VERSION 5.7 ;
BUSBITCHARS "[]" ;
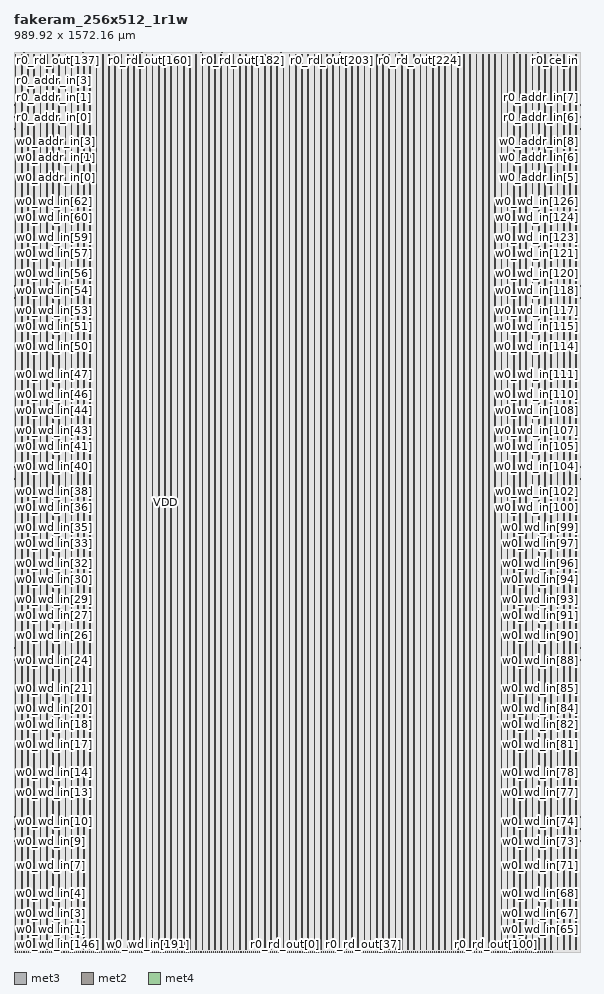
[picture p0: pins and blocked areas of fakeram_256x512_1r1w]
MACRO fakeram_256x512_1r1w
  FOREIGN fakeram_256x512_1r1w 0 0 ;
  SYMMETRY X Y R90 ;
  SIZE 989.920 BY 1572.160 ;
  CLASS BLOCK ;
  PIN w0_wd_in[0]
    DIRECTION INPUT ;
    USE SIGNAL ;
    SHAPE ABUTMENT ;
    PORT
      LAYER met3 ;
      RECT 0.000 3.930 0.900 4.230 ;
    END
  END w0_wd_in[0]
  PIN w0_wd_in[1]
    DIRECTION INPUT ;
    USE SIGNAL ;
    SHAPE ABUTMENT ;
    PORT
      LAYER met3 ;
      RECT 0.000 25.010 0.900 25.310 ;
    END
  END w0_wd_in[1]
  PIN w0_wd_in[2]
    DIRECTION INPUT ;
    USE SIGNAL ;
    SHAPE ABUTMENT ;
    PORT
      LAYER met3 ;
      RECT 0.000 46.090 0.900 46.390 ;
    END
  END w0_wd_in[2]
  PIN w0_wd_in[3]
    DIRECTION INPUT ;
    USE SIGNAL ;
    SHAPE ABUTMENT ;
    PORT
      LAYER met3 ;
      RECT 0.000 67.170 0.900 67.470 ;
    END
  END w0_wd_in[3]
  PIN w0_wd_in[4]
    DIRECTION INPUT ;
    USE SIGNAL ;
    SHAPE ABUTMENT ;
    PORT
      LAYER met3 ;
      RECT 0.000 88.250 0.900 88.550 ;
    END
  END w0_wd_in[4]
  PIN w0_wd_in[5]
    DIRECTION INPUT ;
    USE SIGNAL ;
    SHAPE ABUTMENT ;
    PORT
      LAYER met3 ;
      RECT 0.000 109.330 0.900 109.630 ;
    END
  END w0_wd_in[5]
  PIN w0_wd_in[6]
    DIRECTION INPUT ;
    USE SIGNAL ;
    SHAPE ABUTMENT ;
    PORT
      LAYER met3 ;
      RECT 0.000 130.410 0.900 130.710 ;
    END
  END w0_wd_in[6]
  PIN w0_wd_in[7]
    DIRECTION INPUT ;
    USE SIGNAL ;
    SHAPE ABUTMENT ;
    PORT
      LAYER met3 ;
      RECT 0.000 151.490 0.900 151.790 ;
    END
  END w0_wd_in[7]
  PIN w0_wd_in[8]
    DIRECTION INPUT ;
    USE SIGNAL ;
    SHAPE ABUTMENT ;
    PORT
      LAYER met3 ;
      RECT 0.000 172.570 0.900 172.870 ;
    END
  END w0_wd_in[8]
  PIN w0_wd_in[9]
    DIRECTION INPUT ;
    USE SIGNAL ;
    SHAPE ABUTMENT ;
    PORT
      LAYER met3 ;
      RECT 0.000 193.650 0.900 193.950 ;
    END
  END w0_wd_in[9]
  PIN w0_wd_in[10]
    DIRECTION INPUT ;
    USE SIGNAL ;
    SHAPE ABUTMENT ;
    PORT
      LAYER met3 ;
      RECT 0.000 214.730 0.900 215.030 ;
    END
  END w0_wd_in[10]
  PIN w0_wd_in[11]
    DIRECTION INPUT ;
    USE SIGNAL ;
    SHAPE ABUTMENT ;
    PORT
      LAYER met3 ;
      RECT 0.000 235.810 0.900 236.110 ;
    END
  END w0_wd_in[11]
  PIN w0_wd_in[12]
    DIRECTION INPUT ;
    USE SIGNAL ;
    SHAPE ABUTMENT ;
    PORT
      LAYER met3 ;
      RECT 0.000 256.890 0.900 257.190 ;
    END
  END w0_wd_in[12]
  PIN w0_wd_in[13]
    DIRECTION INPUT ;
    USE SIGNAL ;
    SHAPE ABUTMENT ;
    PORT
      LAYER met3 ;
      RECT 0.000 277.970 0.900 278.270 ;
    END
  END w0_wd_in[13]
  PIN w0_wd_in[14]
    DIRECTION INPUT ;
    USE SIGNAL ;
    SHAPE ABUTMENT ;
    PORT
      LAYER met3 ;
      RECT 0.000 299.050 0.900 299.350 ;
    END
  END w0_wd_in[14]
  PIN w0_wd_in[15]
    DIRECTION INPUT ;
    USE SIGNAL ;
    SHAPE ABUTMENT ;
    PORT
      LAYER met3 ;
      RECT 0.000 320.130 0.900 320.430 ;
    END
  END w0_wd_in[15]
  PIN w0_wd_in[16]
    DIRECTION INPUT ;
    USE SIGNAL ;
    SHAPE ABUTMENT ;
    PORT
      LAYER met3 ;
      RECT 0.000 341.210 0.900 341.510 ;
    END
  END w0_wd_in[16]
  PIN w0_wd_in[17]
    DIRECTION INPUT ;
    USE SIGNAL ;
    SHAPE ABUTMENT ;
    PORT
      LAYER met3 ;
      RECT 0.000 362.290 0.900 362.590 ;
    END
  END w0_wd_in[17]
  PIN w0_wd_in[18]
    DIRECTION INPUT ;
    USE SIGNAL ;
    SHAPE ABUTMENT ;
    PORT
      LAYER met3 ;
      RECT 0.000 383.370 0.900 383.670 ;
    END
  END w0_wd_in[18]
  PIN w0_wd_in[19]
    DIRECTION INPUT ;
    USE SIGNAL ;
    SHAPE ABUTMENT ;
    PORT
      LAYER met3 ;
      RECT 0.000 404.450 0.900 404.750 ;
    END
  END w0_wd_in[19]
  PIN w0_wd_in[20]
    DIRECTION INPUT ;
    USE SIGNAL ;
    SHAPE ABUTMENT ;
    PORT
      LAYER met3 ;
      RECT 0.000 425.530 0.900 425.830 ;
    END
  END w0_wd_in[20]
  PIN w0_wd_in[21]
    DIRECTION INPUT ;
    USE SIGNAL ;
    SHAPE ABUTMENT ;
    PORT
      LAYER met3 ;
      RECT 0.000 446.610 0.900 446.910 ;
    END
  END w0_wd_in[21]
  PIN w0_wd_in[22]
    DIRECTION INPUT ;
    USE SIGNAL ;
    SHAPE ABUTMENT ;
    PORT
      LAYER met3 ;
      RECT 0.000 467.690 0.900 467.990 ;
    END
  END w0_wd_in[22]
  PIN w0_wd_in[23]
    DIRECTION INPUT ;
    USE SIGNAL ;
    SHAPE ABUTMENT ;
    PORT
      LAYER met3 ;
      RECT 0.000 488.770 0.900 489.070 ;
    END
  END w0_wd_in[23]
  PIN w0_wd_in[24]
    DIRECTION INPUT ;
    USE SIGNAL ;
    SHAPE ABUTMENT ;
    PORT
      LAYER met3 ;
      RECT 0.000 509.850 0.900 510.150 ;
    END
  END w0_wd_in[24]
  PIN w0_wd_in[25]
    DIRECTION INPUT ;
    USE SIGNAL ;
    SHAPE ABUTMENT ;
    PORT
      LAYER met3 ;
      RECT 0.000 530.930 0.900 531.230 ;
    END
  END w0_wd_in[25]
  PIN w0_wd_in[26]
    DIRECTION INPUT ;
    USE SIGNAL ;
    SHAPE ABUTMENT ;
    PORT
      LAYER met3 ;
      RECT 0.000 552.010 0.900 552.310 ;
    END
  END w0_wd_in[26]
  PIN w0_wd_in[27]
    DIRECTION INPUT ;
    USE SIGNAL ;
    SHAPE ABUTMENT ;
    PORT
      LAYER met3 ;
      RECT 0.000 573.090 0.900 573.390 ;
    END
  END w0_wd_in[27]
  PIN w0_wd_in[28]
    DIRECTION INPUT ;
    USE SIGNAL ;
    SHAPE ABUTMENT ;
    PORT
      LAYER met3 ;
      RECT 0.000 594.170 0.900 594.470 ;
    END
  END w0_wd_in[28]
  PIN w0_wd_in[29]
    DIRECTION INPUT ;
    USE SIGNAL ;
    SHAPE ABUTMENT ;
    PORT
      LAYER met3 ;
      RECT 0.000 615.250 0.900 615.550 ;
    END
  END w0_wd_in[29]
  PIN w0_wd_in[30]
    DIRECTION INPUT ;
    USE SIGNAL ;
    SHAPE ABUTMENT ;
    PORT
      LAYER met3 ;
      RECT 0.000 636.330 0.900 636.630 ;
    END
  END w0_wd_in[30]
  PIN w0_wd_in[31]
    DIRECTION INPUT ;
    USE SIGNAL ;
    SHAPE ABUTMENT ;
    PORT
      LAYER met3 ;
      RECT 0.000 657.410 0.900 657.710 ;
    END
  END w0_wd_in[31]
  PIN w0_wd_in[32]
    DIRECTION INPUT ;
    USE SIGNAL ;
    SHAPE ABUTMENT ;
    PORT
      LAYER met3 ;
      RECT 0.000 678.490 0.900 678.790 ;
    END
  END w0_wd_in[32]
  PIN w0_wd_in[33]
    DIRECTION INPUT ;
    USE SIGNAL ;
    SHAPE ABUTMENT ;
    PORT
      LAYER met3 ;
      RECT 0.000 699.570 0.900 699.870 ;
    END
  END w0_wd_in[33]
  PIN w0_wd_in[34]
    DIRECTION INPUT ;
    USE SIGNAL ;
    SHAPE ABUTMENT ;
    PORT
      LAYER met3 ;
      RECT 0.000 720.650 0.900 720.950 ;
    END
  END w0_wd_in[34]
  PIN w0_wd_in[35]
    DIRECTION INPUT ;
    USE SIGNAL ;
    SHAPE ABUTMENT ;
    PORT
      LAYER met3 ;
      RECT 0.000 741.730 0.900 742.030 ;
    END
  END w0_wd_in[35]
  PIN w0_wd_in[36]
    DIRECTION INPUT ;
    USE SIGNAL ;
    SHAPE ABUTMENT ;
    PORT
      LAYER met3 ;
      RECT 0.000 762.810 0.900 763.110 ;
    END
  END w0_wd_in[36]
  PIN w0_wd_in[37]
    DIRECTION INPUT ;
    USE SIGNAL ;
    SHAPE ABUTMENT ;
    PORT
      LAYER met3 ;
      RECT 0.000 783.890 0.900 784.190 ;
    END
  END w0_wd_in[37]
  PIN w0_wd_in[38]
    DIRECTION INPUT ;
    USE SIGNAL ;
    SHAPE ABUTMENT ;
    PORT
      LAYER met3 ;
      RECT 0.000 804.970 0.900 805.270 ;
    END
  END w0_wd_in[38]
  PIN w0_wd_in[39]
    DIRECTION INPUT ;
    USE SIGNAL ;
    SHAPE ABUTMENT ;
    PORT
      LAYER met3 ;
      RECT 0.000 826.050 0.900 826.350 ;
    END
  END w0_wd_in[39]
  PIN w0_wd_in[40]
    DIRECTION INPUT ;
    USE SIGNAL ;
    SHAPE ABUTMENT ;
    PORT
      LAYER met3 ;
      RECT 0.000 847.130 0.900 847.430 ;
    END
  END w0_wd_in[40]
  PIN w0_wd_in[41]
    DIRECTION INPUT ;
    USE SIGNAL ;
    SHAPE ABUTMENT ;
    PORT
      LAYER met3 ;
      RECT 0.000 868.210 0.900 868.510 ;
    END
  END w0_wd_in[41]
  PIN w0_wd_in[42]
    DIRECTION INPUT ;
    USE SIGNAL ;
    SHAPE ABUTMENT ;
    PORT
      LAYER met3 ;
      RECT 0.000 889.290 0.900 889.590 ;
    END
  END w0_wd_in[42]
  PIN w0_wd_in[43]
    DIRECTION INPUT ;
    USE SIGNAL ;
    SHAPE ABUTMENT ;
    PORT
      LAYER met3 ;
      RECT 0.000 910.370 0.900 910.670 ;
    END
  END w0_wd_in[43]
  PIN w0_wd_in[44]
    DIRECTION INPUT ;
    USE SIGNAL ;
    SHAPE ABUTMENT ;
    PORT
      LAYER met3 ;
      RECT 0.000 931.450 0.900 931.750 ;
    END
  END w0_wd_in[44]
  PIN w0_wd_in[45]
    DIRECTION INPUT ;
    USE SIGNAL ;
    SHAPE ABUTMENT ;
    PORT
      LAYER met3 ;
      RECT 0.000 952.530 0.900 952.830 ;
    END
  END w0_wd_in[45]
  PIN w0_wd_in[46]
    DIRECTION INPUT ;
    USE SIGNAL ;
    SHAPE ABUTMENT ;
    PORT
      LAYER met3 ;
      RECT 0.000 973.610 0.900 973.910 ;
    END
  END w0_wd_in[46]
  PIN w0_wd_in[47]
    DIRECTION INPUT ;
    USE SIGNAL ;
    SHAPE ABUTMENT ;
    PORT
      LAYER met3 ;
      RECT 0.000 994.690 0.900 994.990 ;
    END
  END w0_wd_in[47]
  PIN w0_wd_in[48]
    DIRECTION INPUT ;
    USE SIGNAL ;
    SHAPE ABUTMENT ;
    PORT
      LAYER met3 ;
      RECT 0.000 1015.770 0.900 1016.070 ;
    END
  END w0_wd_in[48]
  PIN w0_wd_in[49]
    DIRECTION INPUT ;
    USE SIGNAL ;
    SHAPE ABUTMENT ;
    PORT
      LAYER met3 ;
      RECT 0.000 1036.850 0.900 1037.150 ;
    END
  END w0_wd_in[49]
  PIN w0_wd_in[50]
    DIRECTION INPUT ;
    USE SIGNAL ;
    SHAPE ABUTMENT ;
    PORT
      LAYER met3 ;
      RECT 0.000 1057.930 0.900 1058.230 ;
    END
  END w0_wd_in[50]
  PIN w0_wd_in[51]
    DIRECTION INPUT ;
    USE SIGNAL ;
    SHAPE ABUTMENT ;
    PORT
      LAYER met3 ;
      RECT 0.000 1079.010 0.900 1079.310 ;
    END
  END w0_wd_in[51]
  PIN w0_wd_in[52]
    DIRECTION INPUT ;
    USE SIGNAL ;
    SHAPE ABUTMENT ;
    PORT
      LAYER met3 ;
      RECT 0.000 1100.090 0.900 1100.390 ;
    END
  END w0_wd_in[52]
  PIN w0_wd_in[53]
    DIRECTION INPUT ;
    USE SIGNAL ;
    SHAPE ABUTMENT ;
    PORT
      LAYER met3 ;
      RECT 0.000 1121.170 0.900 1121.470 ;
    END
  END w0_wd_in[53]
  PIN w0_wd_in[54]
    DIRECTION INPUT ;
    USE SIGNAL ;
    SHAPE ABUTMENT ;
    PORT
      LAYER met3 ;
      RECT 0.000 1142.250 0.900 1142.550 ;
    END
  END w0_wd_in[54]
  PIN w0_wd_in[55]
    DIRECTION INPUT ;
    USE SIGNAL ;
    SHAPE ABUTMENT ;
    PORT
      LAYER met3 ;
      RECT 0.000 1163.330 0.900 1163.630 ;
    END
  END w0_wd_in[55]
  PIN w0_wd_in[56]
    DIRECTION INPUT ;
    USE SIGNAL ;
    SHAPE ABUTMENT ;
    PORT
      LAYER met3 ;
      RECT 0.000 1184.410 0.900 1184.710 ;
    END
  END w0_wd_in[56]
  PIN w0_wd_in[57]
    DIRECTION INPUT ;
    USE SIGNAL ;
    SHAPE ABUTMENT ;
    PORT
      LAYER met3 ;
      RECT 0.000 1205.490 0.900 1205.790 ;
    END
  END w0_wd_in[57]
  PIN w0_wd_in[58]
    DIRECTION INPUT ;
    USE SIGNAL ;
    SHAPE ABUTMENT ;
    PORT
      LAYER met3 ;
      RECT 0.000 1226.570 0.900 1226.870 ;
    END
  END w0_wd_in[58]
  PIN w0_wd_in[59]
    DIRECTION INPUT ;
    USE SIGNAL ;
    SHAPE ABUTMENT ;
    PORT
      LAYER met3 ;
      RECT 0.000 1247.650 0.900 1247.950 ;
    END
  END w0_wd_in[59]
  PIN w0_wd_in[60]
    DIRECTION INPUT ;
    USE SIGNAL ;
    SHAPE ABUTMENT ;
    PORT
      LAYER met3 ;
      RECT 0.000 1268.730 0.900 1269.030 ;
    END
  END w0_wd_in[60]
  PIN w0_wd_in[61]
    DIRECTION INPUT ;
    USE SIGNAL ;
    SHAPE ABUTMENT ;
    PORT
      LAYER met3 ;
      RECT 0.000 1289.810 0.900 1290.110 ;
    END
  END w0_wd_in[61]
  PIN w0_wd_in[62]
    DIRECTION INPUT ;
    USE SIGNAL ;
    SHAPE ABUTMENT ;
    PORT
      LAYER met3 ;
      RECT 0.000 1310.890 0.900 1311.190 ;
    END
  END w0_wd_in[62]
  PIN w0_wd_in[63]
    DIRECTION INPUT ;
    USE SIGNAL ;
    SHAPE ABUTMENT ;
    PORT
      LAYER met3 ;
      RECT 0.000 1331.970 0.900 1332.270 ;
    END
  END w0_wd_in[63]
  PIN w0_wd_in[64]
    DIRECTION INPUT ;
    USE SIGNAL ;
    SHAPE ABUTMENT ;
    PORT
      LAYER met3 ;
      RECT 989.020 3.930 989.920 4.230 ;
    END
  END w0_wd_in[64]
  PIN w0_wd_in[65]
    DIRECTION INPUT ;
    USE SIGNAL ;
    SHAPE ABUTMENT ;
    PORT
      LAYER met3 ;
      RECT 989.020 25.010 989.920 25.310 ;
    END
  END w0_wd_in[65]
  PIN w0_wd_in[66]
    DIRECTION INPUT ;
    USE SIGNAL ;
    SHAPE ABUTMENT ;
    PORT
      LAYER met3 ;
      RECT 989.020 46.090 989.920 46.390 ;
    END
  END w0_wd_in[66]
  PIN w0_wd_in[67]
    DIRECTION INPUT ;
    USE SIGNAL ;
    SHAPE ABUTMENT ;
    PORT
      LAYER met3 ;
      RECT 989.020 67.170 989.920 67.470 ;
    END
  END w0_wd_in[67]
  PIN w0_wd_in[68]
    DIRECTION INPUT ;
    USE SIGNAL ;
    SHAPE ABUTMENT ;
    PORT
      LAYER met3 ;
      RECT 989.020 88.250 989.920 88.550 ;
    END
  END w0_wd_in[68]
  PIN w0_wd_in[69]
    DIRECTION INPUT ;
    USE SIGNAL ;
    SHAPE ABUTMENT ;
    PORT
      LAYER met3 ;
      RECT 989.020 109.330 989.920 109.630 ;
    END
  END w0_wd_in[69]
  PIN w0_wd_in[70]
    DIRECTION INPUT ;
    USE SIGNAL ;
    SHAPE ABUTMENT ;
    PORT
      LAYER met3 ;
      RECT 989.020 130.410 989.920 130.710 ;
    END
  END w0_wd_in[70]
  PIN w0_wd_in[71]
    DIRECTION INPUT ;
    USE SIGNAL ;
    SHAPE ABUTMENT ;
    PORT
      LAYER met3 ;
      RECT 989.020 151.490 989.920 151.790 ;
    END
  END w0_wd_in[71]
  PIN w0_wd_in[72]
    DIRECTION INPUT ;
    USE SIGNAL ;
    SHAPE ABUTMENT ;
    PORT
      LAYER met3 ;
      RECT 989.020 172.570 989.920 172.870 ;
    END
  END w0_wd_in[72]
  PIN w0_wd_in[73]
    DIRECTION INPUT ;
    USE SIGNAL ;
    SHAPE ABUTMENT ;
    PORT
      LAYER met3 ;
      RECT 989.020 193.650 989.920 193.950 ;
    END
  END w0_wd_in[73]
  PIN w0_wd_in[74]
    DIRECTION INPUT ;
    USE SIGNAL ;
    SHAPE ABUTMENT ;
    PORT
      LAYER met3 ;
      RECT 989.020 214.730 989.920 215.030 ;
    END
  END w0_wd_in[74]
  PIN w0_wd_in[75]
    DIRECTION INPUT ;
    USE SIGNAL ;
    SHAPE ABUTMENT ;
    PORT
      LAYER met3 ;
      RECT 989.020 235.810 989.920 236.110 ;
    END
  END w0_wd_in[75]
  PIN w0_wd_in[76]
    DIRECTION INPUT ;
    USE SIGNAL ;
    SHAPE ABUTMENT ;
    PORT
      LAYER met3 ;
      RECT 989.020 256.890 989.920 257.190 ;
    END
  END w0_wd_in[76]
  PIN w0_wd_in[77]
    DIRECTION INPUT ;
    USE SIGNAL ;
    SHAPE ABUTMENT ;
    PORT
      LAYER met3 ;
      RECT 989.020 277.970 989.920 278.270 ;
    END
  END w0_wd_in[77]
  PIN w0_wd_in[78]
    DIRECTION INPUT ;
    USE SIGNAL ;
    SHAPE ABUTMENT ;
    PORT
      LAYER met3 ;
      RECT 989.020 299.050 989.920 299.350 ;
    END
  END w0_wd_in[78]
  PIN w0_wd_in[79]
    DIRECTION INPUT ;
    USE SIGNAL ;
    SHAPE ABUTMENT ;
    PORT
      LAYER met3 ;
      RECT 989.020 320.130 989.920 320.430 ;
    END
  END w0_wd_in[79]
  PIN w0_wd_in[80]
    DIRECTION INPUT ;
    USE SIGNAL ;
    SHAPE ABUTMENT ;
    PORT
      LAYER met3 ;
      RECT 989.020 341.210 989.920 341.510 ;
    END
  END w0_wd_in[80]
  PIN w0_wd_in[81]
    DIRECTION INPUT ;
    USE SIGNAL ;
    SHAPE ABUTMENT ;
    PORT
      LAYER met3 ;
      RECT 989.020 362.290 989.920 362.590 ;
    END
  END w0_wd_in[81]
  PIN w0_wd_in[82]
    DIRECTION INPUT ;
    USE SIGNAL ;
    SHAPE ABUTMENT ;
    PORT
      LAYER met3 ;
      RECT 989.020 383.370 989.920 383.670 ;
    END
  END w0_wd_in[82]
  PIN w0_wd_in[83]
    DIRECTION INPUT ;
    USE SIGNAL ;
    SHAPE ABUTMENT ;
    PORT
      LAYER met3 ;
      RECT 989.020 404.450 989.920 404.750 ;
    END
  END w0_wd_in[83]
  PIN w0_wd_in[84]
    DIRECTION INPUT ;
    USE SIGNAL ;
    SHAPE ABUTMENT ;
    PORT
      LAYER met3 ;
      RECT 989.020 425.530 989.920 425.830 ;
    END
  END w0_wd_in[84]
  PIN w0_wd_in[85]
    DIRECTION INPUT ;
    USE SIGNAL ;
    SHAPE ABUTMENT ;
    PORT
      LAYER met3 ;
      RECT 989.020 446.610 989.920 446.910 ;
    END
  END w0_wd_in[85]
  PIN w0_wd_in[86]
    DIRECTION INPUT ;
    USE SIGNAL ;
    SHAPE ABUTMENT ;
    PORT
      LAYER met3 ;
      RECT 989.020 467.690 989.920 467.990 ;
    END
  END w0_wd_in[86]
  PIN w0_wd_in[87]
    DIRECTION INPUT ;
    USE SIGNAL ;
    SHAPE ABUTMENT ;
    PORT
      LAYER met3 ;
      RECT 989.020 488.770 989.920 489.070 ;
    END
  END w0_wd_in[87]
  PIN w0_wd_in[88]
    DIRECTION INPUT ;
    USE SIGNAL ;
    SHAPE ABUTMENT ;
    PORT
      LAYER met3 ;
      RECT 989.020 509.850 989.920 510.150 ;
    END
  END w0_wd_in[88]
  PIN w0_wd_in[89]
    DIRECTION INPUT ;
    USE SIGNAL ;
    SHAPE ABUTMENT ;
    PORT
      LAYER met3 ;
      RECT 989.020 530.930 989.920 531.230 ;
    END
  END w0_wd_in[89]
  PIN w0_wd_in[90]
    DIRECTION INPUT ;
    USE SIGNAL ;
    SHAPE ABUTMENT ;
    PORT
      LAYER met3 ;
      RECT 989.020 552.010 989.920 552.310 ;
    END
  END w0_wd_in[90]
  PIN w0_wd_in[91]
    DIRECTION INPUT ;
    USE SIGNAL ;
    SHAPE ABUTMENT ;
    PORT
      LAYER met3 ;
      RECT 989.020 573.090 989.920 573.390 ;
    END
  END w0_wd_in[91]
  PIN w0_wd_in[92]
    DIRECTION INPUT ;
    USE SIGNAL ;
    SHAPE ABUTMENT ;
    PORT
      LAYER met3 ;
      RECT 989.020 594.170 989.920 594.470 ;
    END
  END w0_wd_in[92]
  PIN w0_wd_in[93]
    DIRECTION INPUT ;
    USE SIGNAL ;
    SHAPE ABUTMENT ;
    PORT
      LAYER met3 ;
      RECT 989.020 615.250 989.920 615.550 ;
    END
  END w0_wd_in[93]
  PIN w0_wd_in[94]
    DIRECTION INPUT ;
    USE SIGNAL ;
    SHAPE ABUTMENT ;
    PORT
      LAYER met3 ;
      RECT 989.020 636.330 989.920 636.630 ;
    END
  END w0_wd_in[94]
  PIN w0_wd_in[95]
    DIRECTION INPUT ;
    USE SIGNAL ;
    SHAPE ABUTMENT ;
    PORT
      LAYER met3 ;
      RECT 989.020 657.410 989.920 657.710 ;
    END
  END w0_wd_in[95]
  PIN w0_wd_in[96]
    DIRECTION INPUT ;
    USE SIGNAL ;
    SHAPE ABUTMENT ;
    PORT
      LAYER met3 ;
      RECT 989.020 678.490 989.920 678.790 ;
    END
  END w0_wd_in[96]
  PIN w0_wd_in[97]
    DIRECTION INPUT ;
    USE SIGNAL ;
    SHAPE ABUTMENT ;
    PORT
      LAYER met3 ;
      RECT 989.020 699.570 989.920 699.870 ;
    END
  END w0_wd_in[97]
  PIN w0_wd_in[98]
    DIRECTION INPUT ;
    USE SIGNAL ;
    SHAPE ABUTMENT ;
    PORT
      LAYER met3 ;
      RECT 989.020 720.650 989.920 720.950 ;
    END
  END w0_wd_in[98]
  PIN w0_wd_in[99]
    DIRECTION INPUT ;
    USE SIGNAL ;
    SHAPE ABUTMENT ;
    PORT
      LAYER met3 ;
      RECT 989.020 741.730 989.920 742.030 ;
    END
  END w0_wd_in[99]
  PIN w0_wd_in[100]
    DIRECTION INPUT ;
    USE SIGNAL ;
    SHAPE ABUTMENT ;
    PORT
      LAYER met3 ;
      RECT 989.020 762.810 989.920 763.110 ;
    END
  END w0_wd_in[100]
  PIN w0_wd_in[101]
    DIRECTION INPUT ;
    USE SIGNAL ;
    SHAPE ABUTMENT ;
    PORT
      LAYER met3 ;
      RECT 989.020 783.890 989.920 784.190 ;
    END
  END w0_wd_in[101]
  PIN w0_wd_in[102]
    DIRECTION INPUT ;
    USE SIGNAL ;
    SHAPE ABUTMENT ;
    PORT
      LAYER met3 ;
      RECT 989.020 804.970 989.920 805.270 ;
    END
  END w0_wd_in[102]
  PIN w0_wd_in[103]
    DIRECTION INPUT ;
    USE SIGNAL ;
    SHAPE ABUTMENT ;
    PORT
      LAYER met3 ;
      RECT 989.020 826.050 989.920 826.350 ;
    END
  END w0_wd_in[103]
  PIN w0_wd_in[104]
    DIRECTION INPUT ;
    USE SIGNAL ;
    SHAPE ABUTMENT ;
    PORT
      LAYER met3 ;
      RECT 989.020 847.130 989.920 847.430 ;
    END
  END w0_wd_in[104]
  PIN w0_wd_in[105]
    DIRECTION INPUT ;
    USE SIGNAL ;
    SHAPE ABUTMENT ;
    PORT
      LAYER met3 ;
      RECT 989.020 868.210 989.920 868.510 ;
    END
  END w0_wd_in[105]
  PIN w0_wd_in[106]
    DIRECTION INPUT ;
    USE SIGNAL ;
    SHAPE ABUTMENT ;
    PORT
      LAYER met3 ;
      RECT 989.020 889.290 989.920 889.590 ;
    END
  END w0_wd_in[106]
  PIN w0_wd_in[107]
    DIRECTION INPUT ;
    USE SIGNAL ;
    SHAPE ABUTMENT ;
    PORT
      LAYER met3 ;
      RECT 989.020 910.370 989.920 910.670 ;
    END
  END w0_wd_in[107]
  PIN w0_wd_in[108]
    DIRECTION INPUT ;
    USE SIGNAL ;
    SHAPE ABUTMENT ;
    PORT
      LAYER met3 ;
      RECT 989.020 931.450 989.920 931.750 ;
    END
  END w0_wd_in[108]
  PIN w0_wd_in[109]
    DIRECTION INPUT ;
    USE SIGNAL ;
    SHAPE ABUTMENT ;
    PORT
      LAYER met3 ;
      RECT 989.020 952.530 989.920 952.830 ;
    END
  END w0_wd_in[109]
  PIN w0_wd_in[110]
    DIRECTION INPUT ;
    USE SIGNAL ;
    SHAPE ABUTMENT ;
    PORT
      LAYER met3 ;
      RECT 989.020 973.610 989.920 973.910 ;
    END
  END w0_wd_in[110]
  PIN w0_wd_in[111]
    DIRECTION INPUT ;
    USE SIGNAL ;
    SHAPE ABUTMENT ;
    PORT
      LAYER met3 ;
      RECT 989.020 994.690 989.920 994.990 ;
    END
  END w0_wd_in[111]
  PIN w0_wd_in[112]
    DIRECTION INPUT ;
    USE SIGNAL ;
    SHAPE ABUTMENT ;
    PORT
      LAYER met3 ;
      RECT 989.020 1015.770 989.920 1016.070 ;
    END
  END w0_wd_in[112]
  PIN w0_wd_in[113]
    DIRECTION INPUT ;
    USE SIGNAL ;
    SHAPE ABUTMENT ;
    PORT
      LAYER met3 ;
      RECT 989.020 1036.850 989.920 1037.150 ;
    END
  END w0_wd_in[113]
  PIN w0_wd_in[114]
    DIRECTION INPUT ;
    USE SIGNAL ;
    SHAPE ABUTMENT ;
    PORT
      LAYER met3 ;
      RECT 989.020 1057.930 989.920 1058.230 ;
    END
  END w0_wd_in[114]
  PIN w0_wd_in[115]
    DIRECTION INPUT ;
    USE SIGNAL ;
    SHAPE ABUTMENT ;
    PORT
      LAYER met3 ;
      RECT 989.020 1079.010 989.920 1079.310 ;
    END
  END w0_wd_in[115]
  PIN w0_wd_in[116]
    DIRECTION INPUT ;
    USE SIGNAL ;
    SHAPE ABUTMENT ;
    PORT
      LAYER met3 ;
      RECT 989.020 1100.090 989.920 1100.390 ;
    END
  END w0_wd_in[116]
  PIN w0_wd_in[117]
    DIRECTION INPUT ;
    USE SIGNAL ;
    SHAPE ABUTMENT ;
    PORT
      LAYER met3 ;
      RECT 989.020 1121.170 989.920 1121.470 ;
    END
  END w0_wd_in[117]
  PIN w0_wd_in[118]
    DIRECTION INPUT ;
    USE SIGNAL ;
    SHAPE ABUTMENT ;
    PORT
      LAYER met3 ;
      RECT 989.020 1142.250 989.920 1142.550 ;
    END
  END w0_wd_in[118]
  PIN w0_wd_in[119]
    DIRECTION INPUT ;
    USE SIGNAL ;
    SHAPE ABUTMENT ;
    PORT
      LAYER met3 ;
      RECT 989.020 1163.330 989.920 1163.630 ;
    END
  END w0_wd_in[119]
  PIN w0_wd_in[120]
    DIRECTION INPUT ;
    USE SIGNAL ;
    SHAPE ABUTMENT ;
    PORT
      LAYER met3 ;
      RECT 989.020 1184.410 989.920 1184.710 ;
    END
  END w0_wd_in[120]
  PIN w0_wd_in[121]
    DIRECTION INPUT ;
    USE SIGNAL ;
    SHAPE ABUTMENT ;
    PORT
      LAYER met3 ;
      RECT 989.020 1205.490 989.920 1205.790 ;
    END
  END w0_wd_in[121]
  PIN w0_wd_in[122]
    DIRECTION INPUT ;
    USE SIGNAL ;
    SHAPE ABUTMENT ;
    PORT
      LAYER met3 ;
      RECT 989.020 1226.570 989.920 1226.870 ;
    END
  END w0_wd_in[122]
  PIN w0_wd_in[123]
    DIRECTION INPUT ;
    USE SIGNAL ;
    SHAPE ABUTMENT ;
    PORT
      LAYER met3 ;
      RECT 989.020 1247.650 989.920 1247.950 ;
    END
  END w0_wd_in[123]
  PIN w0_wd_in[124]
    DIRECTION INPUT ;
    USE SIGNAL ;
    SHAPE ABUTMENT ;
    PORT
      LAYER met3 ;
      RECT 989.020 1268.730 989.920 1269.030 ;
    END
  END w0_wd_in[124]
  PIN w0_wd_in[125]
    DIRECTION INPUT ;
    USE SIGNAL ;
    SHAPE ABUTMENT ;
    PORT
      LAYER met3 ;
      RECT 989.020 1289.810 989.920 1290.110 ;
    END
  END w0_wd_in[125]
  PIN w0_wd_in[126]
    DIRECTION INPUT ;
    USE SIGNAL ;
    SHAPE ABUTMENT ;
    PORT
      LAYER met3 ;
      RECT 989.020 1310.890 989.920 1311.190 ;
    END
  END w0_wd_in[126]
  PIN w0_wd_in[127]
    DIRECTION INPUT ;
    USE SIGNAL ;
    SHAPE ABUTMENT ;
    PORT
      LAYER met3 ;
      RECT 989.020 1331.970 989.920 1332.270 ;
    END
  END w0_wd_in[127]
  PIN w0_wd_in[128]
    DIRECTION OUTPUT ;
    USE SIGNAL ;
    SHAPE ABUTMENT ;
    PORT
      LAYER met2 ;
      RECT 2.690 0.000 2.830 0.420 ;
    END
  END w0_wd_in[128]
  PIN w0_wd_in[129]
    DIRECTION OUTPUT ;
    USE SIGNAL ;
    SHAPE ABUTMENT ;
    PORT
      LAYER met2 ;
      RECT 6.370 0.000 6.510 0.420 ;
    END
  END w0_wd_in[129]
  PIN w0_wd_in[130]
    DIRECTION OUTPUT ;
    USE SIGNAL ;
    SHAPE ABUTMENT ;
    PORT
      LAYER met2 ;
      RECT 10.050 0.000 10.190 0.420 ;
    END
  END w0_wd_in[130]
  PIN w0_wd_in[131]
    DIRECTION OUTPUT ;
    USE SIGNAL ;
    SHAPE ABUTMENT ;
    PORT
      LAYER met2 ;
      RECT 13.730 0.000 13.870 0.420 ;
    END
  END w0_wd_in[131]
  PIN w0_wd_in[132]
    DIRECTION OUTPUT ;
    USE SIGNAL ;
    SHAPE ABUTMENT ;
    PORT
      LAYER met2 ;
      RECT 17.410 0.000 17.550 0.420 ;
    END
  END w0_wd_in[132]
  PIN w0_wd_in[133]
    DIRECTION OUTPUT ;
    USE SIGNAL ;
    SHAPE ABUTMENT ;
    PORT
      LAYER met2 ;
      RECT 21.090 0.000 21.230 0.420 ;
    END
  END w0_wd_in[133]
  PIN w0_wd_in[134]
    DIRECTION OUTPUT ;
    USE SIGNAL ;
    SHAPE ABUTMENT ;
    PORT
      LAYER met2 ;
      RECT 24.770 0.000 24.910 0.420 ;
    END
  END w0_wd_in[134]
  PIN w0_wd_in[135]
    DIRECTION OUTPUT ;
    USE SIGNAL ;
    SHAPE ABUTMENT ;
    PORT
      LAYER met2 ;
      RECT 28.450 0.000 28.590 0.420 ;
    END
  END w0_wd_in[135]
  PIN w0_wd_in[136]
    DIRECTION OUTPUT ;
    USE SIGNAL ;
    SHAPE ABUTMENT ;
    PORT
      LAYER met2 ;
      RECT 32.130 0.000 32.270 0.420 ;
    END
  END w0_wd_in[136]
  PIN w0_wd_in[137]
    DIRECTION OUTPUT ;
    USE SIGNAL ;
    SHAPE ABUTMENT ;
    PORT
      LAYER met2 ;
      RECT 35.810 0.000 35.950 0.420 ;
    END
  END w0_wd_in[137]
  PIN w0_wd_in[138]
    DIRECTION OUTPUT ;
    USE SIGNAL ;
    SHAPE ABUTMENT ;
    PORT
      LAYER met2 ;
      RECT 39.490 0.000 39.630 0.420 ;
    END
  END w0_wd_in[138]
  PIN w0_wd_in[139]
    DIRECTION OUTPUT ;
    USE SIGNAL ;
    SHAPE ABUTMENT ;
    PORT
      LAYER met2 ;
      RECT 43.170 0.000 43.310 0.420 ;
    END
  END w0_wd_in[139]
  PIN w0_wd_in[140]
    DIRECTION OUTPUT ;
    USE SIGNAL ;
    SHAPE ABUTMENT ;
    PORT
      LAYER met2 ;
      RECT 46.850 0.000 46.990 0.420 ;
    END
  END w0_wd_in[140]
  PIN w0_wd_in[141]
    DIRECTION OUTPUT ;
    USE SIGNAL ;
    SHAPE ABUTMENT ;
    PORT
      LAYER met2 ;
      RECT 50.530 0.000 50.670 0.420 ;
    END
  END w0_wd_in[141]
  PIN w0_wd_in[142]
    DIRECTION OUTPUT ;
    USE SIGNAL ;
    SHAPE ABUTMENT ;
    PORT
      LAYER met2 ;
      RECT 54.210 0.000 54.350 0.420 ;
    END
  END w0_wd_in[142]
  PIN w0_wd_in[143]
    DIRECTION OUTPUT ;
    USE SIGNAL ;
    SHAPE ABUTMENT ;
    PORT
      LAYER met2 ;
      RECT 57.890 0.000 58.030 0.420 ;
    END
  END w0_wd_in[143]
  PIN w0_wd_in[144]
    DIRECTION OUTPUT ;
    USE SIGNAL ;
    SHAPE ABUTMENT ;
    PORT
      LAYER met2 ;
      RECT 61.570 0.000 61.710 0.420 ;
    END
  END w0_wd_in[144]
  PIN w0_wd_in[145]
    DIRECTION OUTPUT ;
    USE SIGNAL ;
    SHAPE ABUTMENT ;
    PORT
      LAYER met2 ;
      RECT 65.250 0.000 65.390 0.420 ;
    END
  END w0_wd_in[145]
  PIN w0_wd_in[146]
    DIRECTION OUTPUT ;
    USE SIGNAL ;
    SHAPE ABUTMENT ;
    PORT
      LAYER met2 ;
      RECT 68.930 0.000 69.070 0.420 ;
    END
  END w0_wd_in[146]
  PIN w0_wd_in[147]
    DIRECTION OUTPUT ;
    USE SIGNAL ;
    SHAPE ABUTMENT ;
    PORT
      LAYER met2 ;
      RECT 72.610 0.000 72.750 0.420 ;
    END
  END w0_wd_in[147]
  PIN w0_wd_in[148]
    DIRECTION OUTPUT ;
    USE SIGNAL ;
    SHAPE ABUTMENT ;
    PORT
      LAYER met2 ;
      RECT 76.290 0.000 76.430 0.420 ;
    END
  END w0_wd_in[148]
  PIN w0_wd_in[149]
    DIRECTION OUTPUT ;
    USE SIGNAL ;
    SHAPE ABUTMENT ;
    PORT
      LAYER met2 ;
      RECT 79.970 0.000 80.110 0.420 ;
    END
  END w0_wd_in[149]
  PIN w0_wd_in[150]
    DIRECTION OUTPUT ;
    USE SIGNAL ;
    SHAPE ABUTMENT ;
    PORT
      LAYER met2 ;
      RECT 83.650 0.000 83.790 0.420 ;
    END
  END w0_wd_in[150]
  PIN w0_wd_in[151]
    DIRECTION OUTPUT ;
    USE SIGNAL ;
    SHAPE ABUTMENT ;
    PORT
      LAYER met2 ;
      RECT 87.330 0.000 87.470 0.420 ;
    END
  END w0_wd_in[151]
  PIN w0_wd_in[152]
    DIRECTION OUTPUT ;
    USE SIGNAL ;
    SHAPE ABUTMENT ;
    PORT
      LAYER met2 ;
      RECT 91.010 0.000 91.150 0.420 ;
    END
  END w0_wd_in[152]
  PIN w0_wd_in[153]
    DIRECTION OUTPUT ;
    USE SIGNAL ;
    SHAPE ABUTMENT ;
    PORT
      LAYER met2 ;
      RECT 94.690 0.000 94.830 0.420 ;
    END
  END w0_wd_in[153]
  PIN w0_wd_in[154]
    DIRECTION OUTPUT ;
    USE SIGNAL ;
    SHAPE ABUTMENT ;
    PORT
      LAYER met2 ;
      RECT 98.370 0.000 98.510 0.420 ;
    END
  END w0_wd_in[154]
  PIN w0_wd_in[155]
    DIRECTION OUTPUT ;
    USE SIGNAL ;
    SHAPE ABUTMENT ;
    PORT
      LAYER met2 ;
      RECT 102.050 0.000 102.190 0.420 ;
    END
  END w0_wd_in[155]
  PIN w0_wd_in[156]
    DIRECTION OUTPUT ;
    USE SIGNAL ;
    SHAPE ABUTMENT ;
    PORT
      LAYER met2 ;
      RECT 105.730 0.000 105.870 0.420 ;
    END
  END w0_wd_in[156]
  PIN w0_wd_in[157]
    DIRECTION OUTPUT ;
    USE SIGNAL ;
    SHAPE ABUTMENT ;
    PORT
      LAYER met2 ;
      RECT 109.410 0.000 109.550 0.420 ;
    END
  END w0_wd_in[157]
  PIN w0_wd_in[158]
    DIRECTION OUTPUT ;
    USE SIGNAL ;
    SHAPE ABUTMENT ;
    PORT
      LAYER met2 ;
      RECT 113.090 0.000 113.230 0.420 ;
    END
  END w0_wd_in[158]
  PIN w0_wd_in[159]
    DIRECTION OUTPUT ;
    USE SIGNAL ;
    SHAPE ABUTMENT ;
    PORT
      LAYER met2 ;
      RECT 116.770 0.000 116.910 0.420 ;
    END
  END w0_wd_in[159]
  PIN w0_wd_in[160]
    DIRECTION OUTPUT ;
    USE SIGNAL ;
    SHAPE ABUTMENT ;
    PORT
      LAYER met2 ;
      RECT 120.450 0.000 120.590 0.420 ;
    END
  END w0_wd_in[160]
  PIN w0_wd_in[161]
    DIRECTION OUTPUT ;
    USE SIGNAL ;
    SHAPE ABUTMENT ;
    PORT
      LAYER met2 ;
      RECT 124.130 0.000 124.270 0.420 ;
    END
  END w0_wd_in[161]
  PIN w0_wd_in[162]
    DIRECTION OUTPUT ;
    USE SIGNAL ;
    SHAPE ABUTMENT ;
    PORT
      LAYER met2 ;
      RECT 127.810 0.000 127.950 0.420 ;
    END
  END w0_wd_in[162]
  PIN w0_wd_in[163]
    DIRECTION OUTPUT ;
    USE SIGNAL ;
    SHAPE ABUTMENT ;
    PORT
      LAYER met2 ;
      RECT 131.490 0.000 131.630 0.420 ;
    END
  END w0_wd_in[163]
  PIN w0_wd_in[164]
    DIRECTION OUTPUT ;
    USE SIGNAL ;
    SHAPE ABUTMENT ;
    PORT
      LAYER met2 ;
      RECT 135.170 0.000 135.310 0.420 ;
    END
  END w0_wd_in[164]
  PIN w0_wd_in[165]
    DIRECTION OUTPUT ;
    USE SIGNAL ;
    SHAPE ABUTMENT ;
    PORT
      LAYER met2 ;
      RECT 138.850 0.000 138.990 0.420 ;
    END
  END w0_wd_in[165]
  PIN w0_wd_in[166]
    DIRECTION OUTPUT ;
    USE SIGNAL ;
    SHAPE ABUTMENT ;
    PORT
      LAYER met2 ;
      RECT 142.530 0.000 142.670 0.420 ;
    END
  END w0_wd_in[166]
  PIN w0_wd_in[167]
    DIRECTION OUTPUT ;
    USE SIGNAL ;
    SHAPE ABUTMENT ;
    PORT
      LAYER met2 ;
      RECT 146.210 0.000 146.350 0.420 ;
    END
  END w0_wd_in[167]
  PIN w0_wd_in[168]
    DIRECTION OUTPUT ;
    USE SIGNAL ;
    SHAPE ABUTMENT ;
    PORT
      LAYER met2 ;
      RECT 149.890 0.000 150.030 0.420 ;
    END
  END w0_wd_in[168]
  PIN w0_wd_in[169]
    DIRECTION OUTPUT ;
    USE SIGNAL ;
    SHAPE ABUTMENT ;
    PORT
      LAYER met2 ;
      RECT 153.570 0.000 153.710 0.420 ;
    END
  END w0_wd_in[169]
  PIN w0_wd_in[170]
    DIRECTION OUTPUT ;
    USE SIGNAL ;
    SHAPE ABUTMENT ;
    PORT
      LAYER met2 ;
      RECT 157.250 0.000 157.390 0.420 ;
    END
  END w0_wd_in[170]
  PIN w0_wd_in[171]
    DIRECTION OUTPUT ;
    USE SIGNAL ;
    SHAPE ABUTMENT ;
    PORT
      LAYER met2 ;
      RECT 160.930 0.000 161.070 0.420 ;
    END
  END w0_wd_in[171]
  PIN w0_wd_in[172]
    DIRECTION OUTPUT ;
    USE SIGNAL ;
    SHAPE ABUTMENT ;
    PORT
      LAYER met2 ;
      RECT 164.610 0.000 164.750 0.420 ;
    END
  END w0_wd_in[172]
  PIN w0_wd_in[173]
    DIRECTION OUTPUT ;
    USE SIGNAL ;
    SHAPE ABUTMENT ;
    PORT
      LAYER met2 ;
      RECT 168.290 0.000 168.430 0.420 ;
    END
  END w0_wd_in[173]
  PIN w0_wd_in[174]
    DIRECTION OUTPUT ;
    USE SIGNAL ;
    SHAPE ABUTMENT ;
    PORT
      LAYER met2 ;
      RECT 171.970 0.000 172.110 0.420 ;
    END
  END w0_wd_in[174]
  PIN w0_wd_in[175]
    DIRECTION OUTPUT ;
    USE SIGNAL ;
    SHAPE ABUTMENT ;
    PORT
      LAYER met2 ;
      RECT 175.650 0.000 175.790 0.420 ;
    END
  END w0_wd_in[175]
  PIN w0_wd_in[176]
    DIRECTION OUTPUT ;
    USE SIGNAL ;
    SHAPE ABUTMENT ;
    PORT
      LAYER met2 ;
      RECT 179.330 0.000 179.470 0.420 ;
    END
  END w0_wd_in[176]
  PIN w0_wd_in[177]
    DIRECTION OUTPUT ;
    USE SIGNAL ;
    SHAPE ABUTMENT ;
    PORT
      LAYER met2 ;
      RECT 183.010 0.000 183.150 0.420 ;
    END
  END w0_wd_in[177]
  PIN w0_wd_in[178]
    DIRECTION OUTPUT ;
    USE SIGNAL ;
    SHAPE ABUTMENT ;
    PORT
      LAYER met2 ;
      RECT 186.690 0.000 186.830 0.420 ;
    END
  END w0_wd_in[178]
  PIN w0_wd_in[179]
    DIRECTION OUTPUT ;
    USE SIGNAL ;
    SHAPE ABUTMENT ;
    PORT
      LAYER met2 ;
      RECT 190.370 0.000 190.510 0.420 ;
    END
  END w0_wd_in[179]
  PIN w0_wd_in[180]
    DIRECTION OUTPUT ;
    USE SIGNAL ;
    SHAPE ABUTMENT ;
    PORT
      LAYER met2 ;
      RECT 194.050 0.000 194.190 0.420 ;
    END
  END w0_wd_in[180]
  PIN w0_wd_in[181]
    DIRECTION OUTPUT ;
    USE SIGNAL ;
    SHAPE ABUTMENT ;
    PORT
      LAYER met2 ;
      RECT 197.730 0.000 197.870 0.420 ;
    END
  END w0_wd_in[181]
  PIN w0_wd_in[182]
    DIRECTION OUTPUT ;
    USE SIGNAL ;
    SHAPE ABUTMENT ;
    PORT
      LAYER met2 ;
      RECT 201.410 0.000 201.550 0.420 ;
    END
  END w0_wd_in[182]
  PIN w0_wd_in[183]
    DIRECTION OUTPUT ;
    USE SIGNAL ;
    SHAPE ABUTMENT ;
    PORT
      LAYER met2 ;
      RECT 205.090 0.000 205.230 0.420 ;
    END
  END w0_wd_in[183]
  PIN w0_wd_in[184]
    DIRECTION OUTPUT ;
    USE SIGNAL ;
    SHAPE ABUTMENT ;
    PORT
      LAYER met2 ;
      RECT 208.770 0.000 208.910 0.420 ;
    END
  END w0_wd_in[184]
  PIN w0_wd_in[185]
    DIRECTION OUTPUT ;
    USE SIGNAL ;
    SHAPE ABUTMENT ;
    PORT
      LAYER met2 ;
      RECT 212.450 0.000 212.590 0.420 ;
    END
  END w0_wd_in[185]
  PIN w0_wd_in[186]
    DIRECTION OUTPUT ;
    USE SIGNAL ;
    SHAPE ABUTMENT ;
    PORT
      LAYER met2 ;
      RECT 216.130 0.000 216.270 0.420 ;
    END
  END w0_wd_in[186]
  PIN w0_wd_in[187]
    DIRECTION OUTPUT ;
    USE SIGNAL ;
    SHAPE ABUTMENT ;
    PORT
      LAYER met2 ;
      RECT 219.810 0.000 219.950 0.420 ;
    END
  END w0_wd_in[187]
  PIN w0_wd_in[188]
    DIRECTION OUTPUT ;
    USE SIGNAL ;
    SHAPE ABUTMENT ;
    PORT
      LAYER met2 ;
      RECT 223.490 0.000 223.630 0.420 ;
    END
  END w0_wd_in[188]
  PIN w0_wd_in[189]
    DIRECTION OUTPUT ;
    USE SIGNAL ;
    SHAPE ABUTMENT ;
    PORT
      LAYER met2 ;
      RECT 227.170 0.000 227.310 0.420 ;
    END
  END w0_wd_in[189]
  PIN w0_wd_in[190]
    DIRECTION OUTPUT ;
    USE SIGNAL ;
    SHAPE ABUTMENT ;
    PORT
      LAYER met2 ;
      RECT 230.850 0.000 230.990 0.420 ;
    END
  END w0_wd_in[190]
  PIN w0_wd_in[191]
    DIRECTION OUTPUT ;
    USE SIGNAL ;
    SHAPE ABUTMENT ;
    PORT
      LAYER met2 ;
      RECT 234.530 0.000 234.670 0.420 ;
    END
  END w0_wd_in[191]
  PIN w0_wd_in[192]
    DIRECTION OUTPUT ;
    USE SIGNAL ;
    SHAPE ABUTMENT ;
    PORT
      LAYER met2 ;
      RECT 238.210 0.000 238.350 0.420 ;
    END
  END w0_wd_in[192]
  PIN w0_wd_in[193]
    DIRECTION OUTPUT ;
    USE SIGNAL ;
    SHAPE ABUTMENT ;
    PORT
      LAYER met2 ;
      RECT 241.890 0.000 242.030 0.420 ;
    END
  END w0_wd_in[193]
  PIN w0_wd_in[194]
    DIRECTION OUTPUT ;
    USE SIGNAL ;
    SHAPE ABUTMENT ;
    PORT
      LAYER met2 ;
      RECT 245.570 0.000 245.710 0.420 ;
    END
  END w0_wd_in[194]
  PIN w0_wd_in[195]
    DIRECTION OUTPUT ;
    USE SIGNAL ;
    SHAPE ABUTMENT ;
    PORT
      LAYER met2 ;
      RECT 249.250 0.000 249.390 0.420 ;
    END
  END w0_wd_in[195]
  PIN w0_wd_in[196]
    DIRECTION OUTPUT ;
    USE SIGNAL ;
    SHAPE ABUTMENT ;
    PORT
      LAYER met2 ;
      RECT 252.930 0.000 253.070 0.420 ;
    END
  END w0_wd_in[196]
  PIN w0_wd_in[197]
    DIRECTION OUTPUT ;
    USE SIGNAL ;
    SHAPE ABUTMENT ;
    PORT
      LAYER met2 ;
      RECT 256.610 0.000 256.750 0.420 ;
    END
  END w0_wd_in[197]
  PIN w0_wd_in[198]
    DIRECTION OUTPUT ;
    USE SIGNAL ;
    SHAPE ABUTMENT ;
    PORT
      LAYER met2 ;
      RECT 260.290 0.000 260.430 0.420 ;
    END
  END w0_wd_in[198]
  PIN w0_wd_in[199]
    DIRECTION OUTPUT ;
    USE SIGNAL ;
    SHAPE ABUTMENT ;
    PORT
      LAYER met2 ;
      RECT 263.970 0.000 264.110 0.420 ;
    END
  END w0_wd_in[199]
  PIN w0_wd_in[200]
    DIRECTION OUTPUT ;
    USE SIGNAL ;
    SHAPE ABUTMENT ;
    PORT
      LAYER met2 ;
      RECT 267.650 0.000 267.790 0.420 ;
    END
  END w0_wd_in[200]
  PIN w0_wd_in[201]
    DIRECTION OUTPUT ;
    USE SIGNAL ;
    SHAPE ABUTMENT ;
    PORT
      LAYER met2 ;
      RECT 271.330 0.000 271.470 0.420 ;
    END
  END w0_wd_in[201]
  PIN w0_wd_in[202]
    DIRECTION OUTPUT ;
    USE SIGNAL ;
    SHAPE ABUTMENT ;
    PORT
      LAYER met2 ;
      RECT 275.010 0.000 275.150 0.420 ;
    END
  END w0_wd_in[202]
  PIN w0_wd_in[203]
    DIRECTION OUTPUT ;
    USE SIGNAL ;
    SHAPE ABUTMENT ;
    PORT
      LAYER met2 ;
      RECT 278.690 0.000 278.830 0.420 ;
    END
  END w0_wd_in[203]
  PIN w0_wd_in[204]
    DIRECTION OUTPUT ;
    USE SIGNAL ;
    SHAPE ABUTMENT ;
    PORT
      LAYER met2 ;
      RECT 282.370 0.000 282.510 0.420 ;
    END
  END w0_wd_in[204]
  PIN w0_wd_in[205]
    DIRECTION OUTPUT ;
    USE SIGNAL ;
    SHAPE ABUTMENT ;
    PORT
      LAYER met2 ;
      RECT 286.050 0.000 286.190 0.420 ;
    END
  END w0_wd_in[205]
  PIN w0_wd_in[206]
    DIRECTION OUTPUT ;
    USE SIGNAL ;
    SHAPE ABUTMENT ;
    PORT
      LAYER met2 ;
      RECT 289.730 0.000 289.870 0.420 ;
    END
  END w0_wd_in[206]
  PIN w0_wd_in[207]
    DIRECTION OUTPUT ;
    USE SIGNAL ;
    SHAPE ABUTMENT ;
    PORT
      LAYER met2 ;
      RECT 293.410 0.000 293.550 0.420 ;
    END
  END w0_wd_in[207]
  PIN w0_wd_in[208]
    DIRECTION OUTPUT ;
    USE SIGNAL ;
    SHAPE ABUTMENT ;
    PORT
      LAYER met2 ;
      RECT 297.090 0.000 297.230 0.420 ;
    END
  END w0_wd_in[208]
  PIN w0_wd_in[209]
    DIRECTION OUTPUT ;
    USE SIGNAL ;
    SHAPE ABUTMENT ;
    PORT
      LAYER met2 ;
      RECT 300.770 0.000 300.910 0.420 ;
    END
  END w0_wd_in[209]
  PIN w0_wd_in[210]
    DIRECTION OUTPUT ;
    USE SIGNAL ;
    SHAPE ABUTMENT ;
    PORT
      LAYER met2 ;
      RECT 304.450 0.000 304.590 0.420 ;
    END
  END w0_wd_in[210]
  PIN w0_wd_in[211]
    DIRECTION OUTPUT ;
    USE SIGNAL ;
    SHAPE ABUTMENT ;
    PORT
      LAYER met2 ;
      RECT 308.130 0.000 308.270 0.420 ;
    END
  END w0_wd_in[211]
  PIN w0_wd_in[212]
    DIRECTION OUTPUT ;
    USE SIGNAL ;
    SHAPE ABUTMENT ;
    PORT
      LAYER met2 ;
      RECT 311.810 0.000 311.950 0.420 ;
    END
  END w0_wd_in[212]
  PIN w0_wd_in[213]
    DIRECTION OUTPUT ;
    USE SIGNAL ;
    SHAPE ABUTMENT ;
    PORT
      LAYER met2 ;
      RECT 315.490 0.000 315.630 0.420 ;
    END
  END w0_wd_in[213]
  PIN w0_wd_in[214]
    DIRECTION OUTPUT ;
    USE SIGNAL ;
    SHAPE ABUTMENT ;
    PORT
      LAYER met2 ;
      RECT 319.170 0.000 319.310 0.420 ;
    END
  END w0_wd_in[214]
  PIN w0_wd_in[215]
    DIRECTION OUTPUT ;
    USE SIGNAL ;
    SHAPE ABUTMENT ;
    PORT
      LAYER met2 ;
      RECT 322.850 0.000 322.990 0.420 ;
    END
  END w0_wd_in[215]
  PIN w0_wd_in[216]
    DIRECTION OUTPUT ;
    USE SIGNAL ;
    SHAPE ABUTMENT ;
    PORT
      LAYER met2 ;
      RECT 326.530 0.000 326.670 0.420 ;
    END
  END w0_wd_in[216]
  PIN w0_wd_in[217]
    DIRECTION OUTPUT ;
    USE SIGNAL ;
    SHAPE ABUTMENT ;
    PORT
      LAYER met2 ;
      RECT 330.210 0.000 330.350 0.420 ;
    END
  END w0_wd_in[217]
  PIN w0_wd_in[218]
    DIRECTION OUTPUT ;
    USE SIGNAL ;
    SHAPE ABUTMENT ;
    PORT
      LAYER met2 ;
      RECT 333.890 0.000 334.030 0.420 ;
    END
  END w0_wd_in[218]
  PIN w0_wd_in[219]
    DIRECTION OUTPUT ;
    USE SIGNAL ;
    SHAPE ABUTMENT ;
    PORT
      LAYER met2 ;
      RECT 337.570 0.000 337.710 0.420 ;
    END
  END w0_wd_in[219]
  PIN w0_wd_in[220]
    DIRECTION OUTPUT ;
    USE SIGNAL ;
    SHAPE ABUTMENT ;
    PORT
      LAYER met2 ;
      RECT 341.250 0.000 341.390 0.420 ;
    END
  END w0_wd_in[220]
  PIN w0_wd_in[221]
    DIRECTION OUTPUT ;
    USE SIGNAL ;
    SHAPE ABUTMENT ;
    PORT
      LAYER met2 ;
      RECT 344.930 0.000 345.070 0.420 ;
    END
  END w0_wd_in[221]
  PIN w0_wd_in[222]
    DIRECTION OUTPUT ;
    USE SIGNAL ;
    SHAPE ABUTMENT ;
    PORT
      LAYER met2 ;
      RECT 348.610 0.000 348.750 0.420 ;
    END
  END w0_wd_in[222]
  PIN w0_wd_in[223]
    DIRECTION OUTPUT ;
    USE SIGNAL ;
    SHAPE ABUTMENT ;
    PORT
      LAYER met2 ;
      RECT 352.290 0.000 352.430 0.420 ;
    END
  END w0_wd_in[223]
  PIN w0_wd_in[224]
    DIRECTION OUTPUT ;
    USE SIGNAL ;
    SHAPE ABUTMENT ;
    PORT
      LAYER met2 ;
      RECT 355.970 0.000 356.110 0.420 ;
    END
  END w0_wd_in[224]
  PIN w0_wd_in[225]
    DIRECTION OUTPUT ;
    USE SIGNAL ;
    SHAPE ABUTMENT ;
    PORT
      LAYER met2 ;
      RECT 359.650 0.000 359.790 0.420 ;
    END
  END w0_wd_in[225]
  PIN w0_wd_in[226]
    DIRECTION OUTPUT ;
    USE SIGNAL ;
    SHAPE ABUTMENT ;
    PORT
      LAYER met2 ;
      RECT 363.330 0.000 363.470 0.420 ;
    END
  END w0_wd_in[226]
  PIN w0_wd_in[227]
    DIRECTION OUTPUT ;
    USE SIGNAL ;
    SHAPE ABUTMENT ;
    PORT
      LAYER met2 ;
      RECT 367.010 0.000 367.150 0.420 ;
    END
  END w0_wd_in[227]
  PIN w0_wd_in[228]
    DIRECTION OUTPUT ;
    USE SIGNAL ;
    SHAPE ABUTMENT ;
    PORT
      LAYER met2 ;
      RECT 370.690 0.000 370.830 0.420 ;
    END
  END w0_wd_in[228]
  PIN w0_wd_in[229]
    DIRECTION OUTPUT ;
    USE SIGNAL ;
    SHAPE ABUTMENT ;
    PORT
      LAYER met2 ;
      RECT 374.370 0.000 374.510 0.420 ;
    END
  END w0_wd_in[229]
  PIN w0_wd_in[230]
    DIRECTION OUTPUT ;
    USE SIGNAL ;
    SHAPE ABUTMENT ;
    PORT
      LAYER met2 ;
      RECT 378.050 0.000 378.190 0.420 ;
    END
  END w0_wd_in[230]
  PIN w0_wd_in[231]
    DIRECTION OUTPUT ;
    USE SIGNAL ;
    SHAPE ABUTMENT ;
    PORT
      LAYER met2 ;
      RECT 381.730 0.000 381.870 0.420 ;
    END
  END w0_wd_in[231]
  PIN w0_wd_in[232]
    DIRECTION OUTPUT ;
    USE SIGNAL ;
    SHAPE ABUTMENT ;
    PORT
      LAYER met2 ;
      RECT 385.410 0.000 385.550 0.420 ;
    END
  END w0_wd_in[232]
  PIN w0_wd_in[233]
    DIRECTION OUTPUT ;
    USE SIGNAL ;
    SHAPE ABUTMENT ;
    PORT
      LAYER met2 ;
      RECT 389.090 0.000 389.230 0.420 ;
    END
  END w0_wd_in[233]
  PIN w0_wd_in[234]
    DIRECTION OUTPUT ;
    USE SIGNAL ;
    SHAPE ABUTMENT ;
    PORT
      LAYER met2 ;
      RECT 392.770 0.000 392.910 0.420 ;
    END
  END w0_wd_in[234]
  PIN w0_wd_in[235]
    DIRECTION OUTPUT ;
    USE SIGNAL ;
    SHAPE ABUTMENT ;
    PORT
      LAYER met2 ;
      RECT 396.450 0.000 396.590 0.420 ;
    END
  END w0_wd_in[235]
  PIN w0_wd_in[236]
    DIRECTION OUTPUT ;
    USE SIGNAL ;
    SHAPE ABUTMENT ;
    PORT
      LAYER met2 ;
      RECT 400.130 0.000 400.270 0.420 ;
    END
  END w0_wd_in[236]
  PIN w0_wd_in[237]
    DIRECTION OUTPUT ;
    USE SIGNAL ;
    SHAPE ABUTMENT ;
    PORT
      LAYER met2 ;
      RECT 403.810 0.000 403.950 0.420 ;
    END
  END w0_wd_in[237]
  PIN w0_wd_in[238]
    DIRECTION OUTPUT ;
    USE SIGNAL ;
    SHAPE ABUTMENT ;
    PORT
      LAYER met2 ;
      RECT 407.490 0.000 407.630 0.420 ;
    END
  END w0_wd_in[238]
  PIN w0_wd_in[239]
    DIRECTION OUTPUT ;
    USE SIGNAL ;
    SHAPE ABUTMENT ;
    PORT
      LAYER met2 ;
      RECT 411.170 0.000 411.310 0.420 ;
    END
  END w0_wd_in[239]
  PIN w0_wd_in[240]
    DIRECTION OUTPUT ;
    USE SIGNAL ;
    SHAPE ABUTMENT ;
    PORT
      LAYER met2 ;
      RECT 414.850 0.000 414.990 0.420 ;
    END
  END w0_wd_in[240]
  PIN w0_wd_in[241]
    DIRECTION OUTPUT ;
    USE SIGNAL ;
    SHAPE ABUTMENT ;
    PORT
      LAYER met2 ;
      RECT 418.530 0.000 418.670 0.420 ;
    END
  END w0_wd_in[241]
  PIN w0_wd_in[242]
    DIRECTION OUTPUT ;
    USE SIGNAL ;
    SHAPE ABUTMENT ;
    PORT
      LAYER met2 ;
      RECT 422.210 0.000 422.350 0.420 ;
    END
  END w0_wd_in[242]
  PIN w0_wd_in[243]
    DIRECTION OUTPUT ;
    USE SIGNAL ;
    SHAPE ABUTMENT ;
    PORT
      LAYER met2 ;
      RECT 425.890 0.000 426.030 0.420 ;
    END
  END w0_wd_in[243]
  PIN w0_wd_in[244]
    DIRECTION OUTPUT ;
    USE SIGNAL ;
    SHAPE ABUTMENT ;
    PORT
      LAYER met2 ;
      RECT 429.570 0.000 429.710 0.420 ;
    END
  END w0_wd_in[244]
  PIN w0_wd_in[245]
    DIRECTION OUTPUT ;
    USE SIGNAL ;
    SHAPE ABUTMENT ;
    PORT
      LAYER met2 ;
      RECT 433.250 0.000 433.390 0.420 ;
    END
  END w0_wd_in[245]
  PIN w0_wd_in[246]
    DIRECTION OUTPUT ;
    USE SIGNAL ;
    SHAPE ABUTMENT ;
    PORT
      LAYER met2 ;
      RECT 436.930 0.000 437.070 0.420 ;
    END
  END w0_wd_in[246]
  PIN w0_wd_in[247]
    DIRECTION OUTPUT ;
    USE SIGNAL ;
    SHAPE ABUTMENT ;
    PORT
      LAYER met2 ;
      RECT 440.610 0.000 440.750 0.420 ;
    END
  END w0_wd_in[247]
  PIN w0_wd_in[248]
    DIRECTION OUTPUT ;
    USE SIGNAL ;
    SHAPE ABUTMENT ;
    PORT
      LAYER met2 ;
      RECT 444.290 0.000 444.430 0.420 ;
    END
  END w0_wd_in[248]
  PIN w0_wd_in[249]
    DIRECTION OUTPUT ;
    USE SIGNAL ;
    SHAPE ABUTMENT ;
    PORT
      LAYER met2 ;
      RECT 447.970 0.000 448.110 0.420 ;
    END
  END w0_wd_in[249]
  PIN w0_wd_in[250]
    DIRECTION OUTPUT ;
    USE SIGNAL ;
    SHAPE ABUTMENT ;
    PORT
      LAYER met2 ;
      RECT 451.650 0.000 451.790 0.420 ;
    END
  END w0_wd_in[250]
  PIN w0_wd_in[251]
    DIRECTION OUTPUT ;
    USE SIGNAL ;
    SHAPE ABUTMENT ;
    PORT
      LAYER met2 ;
      RECT 455.330 0.000 455.470 0.420 ;
    END
  END w0_wd_in[251]
  PIN w0_wd_in[252]
    DIRECTION OUTPUT ;
    USE SIGNAL ;
    SHAPE ABUTMENT ;
    PORT
      LAYER met2 ;
      RECT 459.010 0.000 459.150 0.420 ;
    END
  END w0_wd_in[252]
  PIN w0_wd_in[253]
    DIRECTION OUTPUT ;
    USE SIGNAL ;
    SHAPE ABUTMENT ;
    PORT
      LAYER met2 ;
      RECT 462.690 0.000 462.830 0.420 ;
    END
  END w0_wd_in[253]
  PIN w0_wd_in[254]
    DIRECTION OUTPUT ;
    USE SIGNAL ;
    SHAPE ABUTMENT ;
    PORT
      LAYER met2 ;
      RECT 466.370 0.000 466.510 0.420 ;
    END
  END w0_wd_in[254]
  PIN w0_wd_in[255]
    DIRECTION OUTPUT ;
    USE SIGNAL ;
    SHAPE ABUTMENT ;
    PORT
      LAYER met2 ;
      RECT 470.050 0.000 470.190 0.420 ;
    END
  END w0_wd_in[255]
  PIN r0_rd_out[0]
    DIRECTION OUTPUT ;
    USE SIGNAL ;
    SHAPE ABUTMENT ;
    PORT
      LAYER met2 ;
      RECT 473.730 0.000 473.870 0.420 ;
    END
  END r0_rd_out[0]
  PIN r0_rd_out[1]
    DIRECTION OUTPUT ;
    USE SIGNAL ;
    SHAPE ABUTMENT ;
    PORT
      LAYER met2 ;
      RECT 477.410 0.000 477.550 0.420 ;
    END
  END r0_rd_out[1]
  PIN r0_rd_out[2]
    DIRECTION OUTPUT ;
    USE SIGNAL ;
    SHAPE ABUTMENT ;
    PORT
      LAYER met2 ;
      RECT 481.090 0.000 481.230 0.420 ;
    END
  END r0_rd_out[2]
  PIN r0_rd_out[3]
    DIRECTION OUTPUT ;
    USE SIGNAL ;
    SHAPE ABUTMENT ;
    PORT
      LAYER met2 ;
      RECT 484.770 0.000 484.910 0.420 ;
    END
  END r0_rd_out[3]
  PIN r0_rd_out[4]
    DIRECTION OUTPUT ;
    USE SIGNAL ;
    SHAPE ABUTMENT ;
    PORT
      LAYER met2 ;
      RECT 488.450 0.000 488.590 0.420 ;
    END
  END r0_rd_out[4]
  PIN r0_rd_out[5]
    DIRECTION OUTPUT ;
    USE SIGNAL ;
    SHAPE ABUTMENT ;
    PORT
      LAYER met2 ;
      RECT 492.130 0.000 492.270 0.420 ;
    END
  END r0_rd_out[5]
  PIN r0_rd_out[6]
    DIRECTION OUTPUT ;
    USE SIGNAL ;
    SHAPE ABUTMENT ;
    PORT
      LAYER met2 ;
      RECT 495.810 0.000 495.950 0.420 ;
    END
  END r0_rd_out[6]
  PIN r0_rd_out[7]
    DIRECTION OUTPUT ;
    USE SIGNAL ;
    SHAPE ABUTMENT ;
    PORT
      LAYER met2 ;
      RECT 499.490 0.000 499.630 0.420 ;
    END
  END r0_rd_out[7]
  PIN r0_rd_out[8]
    DIRECTION OUTPUT ;
    USE SIGNAL ;
    SHAPE ABUTMENT ;
    PORT
      LAYER met2 ;
      RECT 503.170 0.000 503.310 0.420 ;
    END
  END r0_rd_out[8]
  PIN r0_rd_out[9]
    DIRECTION OUTPUT ;
    USE SIGNAL ;
    SHAPE ABUTMENT ;
    PORT
      LAYER met2 ;
      RECT 506.850 0.000 506.990 0.420 ;
    END
  END r0_rd_out[9]
  PIN r0_rd_out[10]
    DIRECTION OUTPUT ;
    USE SIGNAL ;
    SHAPE ABUTMENT ;
    PORT
      LAYER met2 ;
      RECT 510.530 0.000 510.670 0.420 ;
    END
  END r0_rd_out[10]
  PIN r0_rd_out[11]
    DIRECTION OUTPUT ;
    USE SIGNAL ;
    SHAPE ABUTMENT ;
    PORT
      LAYER met2 ;
      RECT 514.210 0.000 514.350 0.420 ;
    END
  END r0_rd_out[11]
  PIN r0_rd_out[12]
    DIRECTION OUTPUT ;
    USE SIGNAL ;
    SHAPE ABUTMENT ;
    PORT
      LAYER met2 ;
      RECT 517.890 0.000 518.030 0.420 ;
    END
  END r0_rd_out[12]
  PIN r0_rd_out[13]
    DIRECTION OUTPUT ;
    USE SIGNAL ;
    SHAPE ABUTMENT ;
    PORT
      LAYER met2 ;
      RECT 521.570 0.000 521.710 0.420 ;
    END
  END r0_rd_out[13]
  PIN r0_rd_out[14]
    DIRECTION OUTPUT ;
    USE SIGNAL ;
    SHAPE ABUTMENT ;
    PORT
      LAYER met2 ;
      RECT 525.250 0.000 525.390 0.420 ;
    END
  END r0_rd_out[14]
  PIN r0_rd_out[15]
    DIRECTION OUTPUT ;
    USE SIGNAL ;
    SHAPE ABUTMENT ;
    PORT
      LAYER met2 ;
      RECT 528.930 0.000 529.070 0.420 ;
    END
  END r0_rd_out[15]
  PIN r0_rd_out[16]
    DIRECTION OUTPUT ;
    USE SIGNAL ;
    SHAPE ABUTMENT ;
    PORT
      LAYER met2 ;
      RECT 532.610 0.000 532.750 0.420 ;
    END
  END r0_rd_out[16]
  PIN r0_rd_out[17]
    DIRECTION OUTPUT ;
    USE SIGNAL ;
    SHAPE ABUTMENT ;
    PORT
      LAYER met2 ;
      RECT 536.290 0.000 536.430 0.420 ;
    END
  END r0_rd_out[17]
  PIN r0_rd_out[18]
    DIRECTION OUTPUT ;
    USE SIGNAL ;
    SHAPE ABUTMENT ;
    PORT
      LAYER met2 ;
      RECT 539.970 0.000 540.110 0.420 ;
    END
  END r0_rd_out[18]
  PIN r0_rd_out[19]
    DIRECTION OUTPUT ;
    USE SIGNAL ;
    SHAPE ABUTMENT ;
    PORT
      LAYER met2 ;
      RECT 543.650 0.000 543.790 0.420 ;
    END
  END r0_rd_out[19]
  PIN r0_rd_out[20]
    DIRECTION OUTPUT ;
    USE SIGNAL ;
    SHAPE ABUTMENT ;
    PORT
      LAYER met2 ;
      RECT 547.330 0.000 547.470 0.420 ;
    END
  END r0_rd_out[20]
  PIN r0_rd_out[21]
    DIRECTION OUTPUT ;
    USE SIGNAL ;
    SHAPE ABUTMENT ;
    PORT
      LAYER met2 ;
      RECT 551.010 0.000 551.150 0.420 ;
    END
  END r0_rd_out[21]
  PIN r0_rd_out[22]
    DIRECTION OUTPUT ;
    USE SIGNAL ;
    SHAPE ABUTMENT ;
    PORT
      LAYER met2 ;
      RECT 554.690 0.000 554.830 0.420 ;
    END
  END r0_rd_out[22]
  PIN r0_rd_out[23]
    DIRECTION OUTPUT ;
    USE SIGNAL ;
    SHAPE ABUTMENT ;
    PORT
      LAYER met2 ;
      RECT 558.370 0.000 558.510 0.420 ;
    END
  END r0_rd_out[23]
  PIN r0_rd_out[24]
    DIRECTION OUTPUT ;
    USE SIGNAL ;
    SHAPE ABUTMENT ;
    PORT
      LAYER met2 ;
      RECT 562.050 0.000 562.190 0.420 ;
    END
  END r0_rd_out[24]
  PIN r0_rd_out[25]
    DIRECTION OUTPUT ;
    USE SIGNAL ;
    SHAPE ABUTMENT ;
    PORT
      LAYER met2 ;
      RECT 565.730 0.000 565.870 0.420 ;
    END
  END r0_rd_out[25]
  PIN r0_rd_out[26]
    DIRECTION OUTPUT ;
    USE SIGNAL ;
    SHAPE ABUTMENT ;
    PORT
      LAYER met2 ;
      RECT 569.410 0.000 569.550 0.420 ;
    END
  END r0_rd_out[26]
  PIN r0_rd_out[27]
    DIRECTION OUTPUT ;
    USE SIGNAL ;
    SHAPE ABUTMENT ;
    PORT
      LAYER met2 ;
      RECT 573.090 0.000 573.230 0.420 ;
    END
  END r0_rd_out[27]
  PIN r0_rd_out[28]
    DIRECTION OUTPUT ;
    USE SIGNAL ;
    SHAPE ABUTMENT ;
    PORT
      LAYER met2 ;
      RECT 576.770 0.000 576.910 0.420 ;
    END
  END r0_rd_out[28]
  PIN r0_rd_out[29]
    DIRECTION OUTPUT ;
    USE SIGNAL ;
    SHAPE ABUTMENT ;
    PORT
      LAYER met2 ;
      RECT 580.450 0.000 580.590 0.420 ;
    END
  END r0_rd_out[29]
  PIN r0_rd_out[30]
    DIRECTION OUTPUT ;
    USE SIGNAL ;
    SHAPE ABUTMENT ;
    PORT
      LAYER met2 ;
      RECT 584.130 0.000 584.270 0.420 ;
    END
  END r0_rd_out[30]
  PIN r0_rd_out[31]
    DIRECTION OUTPUT ;
    USE SIGNAL ;
    SHAPE ABUTMENT ;
    PORT
      LAYER met2 ;
      RECT 587.810 0.000 587.950 0.420 ;
    END
  END r0_rd_out[31]
  PIN r0_rd_out[32]
    DIRECTION OUTPUT ;
    USE SIGNAL ;
    SHAPE ABUTMENT ;
    PORT
      LAYER met2 ;
      RECT 591.490 0.000 591.630 0.420 ;
    END
  END r0_rd_out[32]
  PIN r0_rd_out[33]
    DIRECTION OUTPUT ;
    USE SIGNAL ;
    SHAPE ABUTMENT ;
    PORT
      LAYER met2 ;
      RECT 595.170 0.000 595.310 0.420 ;
    END
  END r0_rd_out[33]
  PIN r0_rd_out[34]
    DIRECTION OUTPUT ;
    USE SIGNAL ;
    SHAPE ABUTMENT ;
    PORT
      LAYER met2 ;
      RECT 598.850 0.000 598.990 0.420 ;
    END
  END r0_rd_out[34]
  PIN r0_rd_out[35]
    DIRECTION OUTPUT ;
    USE SIGNAL ;
    SHAPE ABUTMENT ;
    PORT
      LAYER met2 ;
      RECT 602.530 0.000 602.670 0.420 ;
    END
  END r0_rd_out[35]
  PIN r0_rd_out[36]
    DIRECTION OUTPUT ;
    USE SIGNAL ;
    SHAPE ABUTMENT ;
    PORT
      LAYER met2 ;
      RECT 606.210 0.000 606.350 0.420 ;
    END
  END r0_rd_out[36]
  PIN r0_rd_out[37]
    DIRECTION OUTPUT ;
    USE SIGNAL ;
    SHAPE ABUTMENT ;
    PORT
      LAYER met2 ;
      RECT 609.890 0.000 610.030 0.420 ;
    END
  END r0_rd_out[37]
  PIN r0_rd_out[38]
    DIRECTION OUTPUT ;
    USE SIGNAL ;
    SHAPE ABUTMENT ;
    PORT
      LAYER met2 ;
      RECT 613.570 0.000 613.710 0.420 ;
    END
  END r0_rd_out[38]
  PIN r0_rd_out[39]
    DIRECTION OUTPUT ;
    USE SIGNAL ;
    SHAPE ABUTMENT ;
    PORT
      LAYER met2 ;
      RECT 617.250 0.000 617.390 0.420 ;
    END
  END r0_rd_out[39]
  PIN r0_rd_out[40]
    DIRECTION OUTPUT ;
    USE SIGNAL ;
    SHAPE ABUTMENT ;
    PORT
      LAYER met2 ;
      RECT 620.930 0.000 621.070 0.420 ;
    END
  END r0_rd_out[40]
  PIN r0_rd_out[41]
    DIRECTION OUTPUT ;
    USE SIGNAL ;
    SHAPE ABUTMENT ;
    PORT
      LAYER met2 ;
      RECT 624.610 0.000 624.750 0.420 ;
    END
  END r0_rd_out[41]
  PIN r0_rd_out[42]
    DIRECTION OUTPUT ;
    USE SIGNAL ;
    SHAPE ABUTMENT ;
    PORT
      LAYER met2 ;
      RECT 628.290 0.000 628.430 0.420 ;
    END
  END r0_rd_out[42]
  PIN r0_rd_out[43]
    DIRECTION OUTPUT ;
    USE SIGNAL ;
    SHAPE ABUTMENT ;
    PORT
      LAYER met2 ;
      RECT 631.970 0.000 632.110 0.420 ;
    END
  END r0_rd_out[43]
  PIN r0_rd_out[44]
    DIRECTION OUTPUT ;
    USE SIGNAL ;
    SHAPE ABUTMENT ;
    PORT
      LAYER met2 ;
      RECT 635.650 0.000 635.790 0.420 ;
    END
  END r0_rd_out[44]
  PIN r0_rd_out[45]
    DIRECTION OUTPUT ;
    USE SIGNAL ;
    SHAPE ABUTMENT ;
    PORT
      LAYER met2 ;
      RECT 639.330 0.000 639.470 0.420 ;
    END
  END r0_rd_out[45]
  PIN r0_rd_out[46]
    DIRECTION OUTPUT ;
    USE SIGNAL ;
    SHAPE ABUTMENT ;
    PORT
      LAYER met2 ;
      RECT 643.010 0.000 643.150 0.420 ;
    END
  END r0_rd_out[46]
  PIN r0_rd_out[47]
    DIRECTION OUTPUT ;
    USE SIGNAL ;
    SHAPE ABUTMENT ;
    PORT
      LAYER met2 ;
      RECT 646.690 0.000 646.830 0.420 ;
    END
  END r0_rd_out[47]
  PIN r0_rd_out[48]
    DIRECTION OUTPUT ;
    USE SIGNAL ;
    SHAPE ABUTMENT ;
    PORT
      LAYER met2 ;
      RECT 650.370 0.000 650.510 0.420 ;
    END
  END r0_rd_out[48]
  PIN r0_rd_out[49]
    DIRECTION OUTPUT ;
    USE SIGNAL ;
    SHAPE ABUTMENT ;
    PORT
      LAYER met2 ;
      RECT 654.050 0.000 654.190 0.420 ;
    END
  END r0_rd_out[49]
  PIN r0_rd_out[50]
    DIRECTION OUTPUT ;
    USE SIGNAL ;
    SHAPE ABUTMENT ;
    PORT
      LAYER met2 ;
      RECT 657.730 0.000 657.870 0.420 ;
    END
  END r0_rd_out[50]
  PIN r0_rd_out[51]
    DIRECTION OUTPUT ;
    USE SIGNAL ;
    SHAPE ABUTMENT ;
    PORT
      LAYER met2 ;
      RECT 661.410 0.000 661.550 0.420 ;
    END
  END r0_rd_out[51]
  PIN r0_rd_out[52]
    DIRECTION OUTPUT ;
    USE SIGNAL ;
    SHAPE ABUTMENT ;
    PORT
      LAYER met2 ;
      RECT 665.090 0.000 665.230 0.420 ;
    END
  END r0_rd_out[52]
  PIN r0_rd_out[53]
    DIRECTION OUTPUT ;
    USE SIGNAL ;
    SHAPE ABUTMENT ;
    PORT
      LAYER met2 ;
      RECT 668.770 0.000 668.910 0.420 ;
    END
  END r0_rd_out[53]
  PIN r0_rd_out[54]
    DIRECTION OUTPUT ;
    USE SIGNAL ;
    SHAPE ABUTMENT ;
    PORT
      LAYER met2 ;
      RECT 672.450 0.000 672.590 0.420 ;
    END
  END r0_rd_out[54]
  PIN r0_rd_out[55]
    DIRECTION OUTPUT ;
    USE SIGNAL ;
    SHAPE ABUTMENT ;
    PORT
      LAYER met2 ;
      RECT 676.130 0.000 676.270 0.420 ;
    END
  END r0_rd_out[55]
  PIN r0_rd_out[56]
    DIRECTION OUTPUT ;
    USE SIGNAL ;
    SHAPE ABUTMENT ;
    PORT
      LAYER met2 ;
      RECT 679.810 0.000 679.950 0.420 ;
    END
  END r0_rd_out[56]
  PIN r0_rd_out[57]
    DIRECTION OUTPUT ;
    USE SIGNAL ;
    SHAPE ABUTMENT ;
    PORT
      LAYER met2 ;
      RECT 683.490 0.000 683.630 0.420 ;
    END
  END r0_rd_out[57]
  PIN r0_rd_out[58]
    DIRECTION OUTPUT ;
    USE SIGNAL ;
    SHAPE ABUTMENT ;
    PORT
      LAYER met2 ;
      RECT 687.170 0.000 687.310 0.420 ;
    END
  END r0_rd_out[58]
  PIN r0_rd_out[59]
    DIRECTION OUTPUT ;
    USE SIGNAL ;
    SHAPE ABUTMENT ;
    PORT
      LAYER met2 ;
      RECT 690.850 0.000 690.990 0.420 ;
    END
  END r0_rd_out[59]
  PIN r0_rd_out[60]
    DIRECTION OUTPUT ;
    USE SIGNAL ;
    SHAPE ABUTMENT ;
    PORT
      LAYER met2 ;
      RECT 694.530 0.000 694.670 0.420 ;
    END
  END r0_rd_out[60]
  PIN r0_rd_out[61]
    DIRECTION OUTPUT ;
    USE SIGNAL ;
    SHAPE ABUTMENT ;
    PORT
      LAYER met2 ;
      RECT 698.210 0.000 698.350 0.420 ;
    END
  END r0_rd_out[61]
  PIN r0_rd_out[62]
    DIRECTION OUTPUT ;
    USE SIGNAL ;
    SHAPE ABUTMENT ;
    PORT
      LAYER met2 ;
      RECT 701.890 0.000 702.030 0.420 ;
    END
  END r0_rd_out[62]
  PIN r0_rd_out[63]
    DIRECTION OUTPUT ;
    USE SIGNAL ;
    SHAPE ABUTMENT ;
    PORT
      LAYER met2 ;
      RECT 705.570 0.000 705.710 0.420 ;
    END
  END r0_rd_out[63]
  PIN r0_rd_out[64]
    DIRECTION OUTPUT ;
    USE SIGNAL ;
    SHAPE ABUTMENT ;
    PORT
      LAYER met2 ;
      RECT 709.250 0.000 709.390 0.420 ;
    END
  END r0_rd_out[64]
  PIN r0_rd_out[65]
    DIRECTION OUTPUT ;
    USE SIGNAL ;
    SHAPE ABUTMENT ;
    PORT
      LAYER met2 ;
      RECT 712.930 0.000 713.070 0.420 ;
    END
  END r0_rd_out[65]
  PIN r0_rd_out[66]
    DIRECTION OUTPUT ;
    USE SIGNAL ;
    SHAPE ABUTMENT ;
    PORT
      LAYER met2 ;
      RECT 716.610 0.000 716.750 0.420 ;
    END
  END r0_rd_out[66]
  PIN r0_rd_out[67]
    DIRECTION OUTPUT ;
    USE SIGNAL ;
    SHAPE ABUTMENT ;
    PORT
      LAYER met2 ;
      RECT 720.290 0.000 720.430 0.420 ;
    END
  END r0_rd_out[67]
  PIN r0_rd_out[68]
    DIRECTION OUTPUT ;
    USE SIGNAL ;
    SHAPE ABUTMENT ;
    PORT
      LAYER met2 ;
      RECT 723.970 0.000 724.110 0.420 ;
    END
  END r0_rd_out[68]
  PIN r0_rd_out[69]
    DIRECTION OUTPUT ;
    USE SIGNAL ;
    SHAPE ABUTMENT ;
    PORT
      LAYER met2 ;
      RECT 727.650 0.000 727.790 0.420 ;
    END
  END r0_rd_out[69]
  PIN r0_rd_out[70]
    DIRECTION OUTPUT ;
    USE SIGNAL ;
    SHAPE ABUTMENT ;
    PORT
      LAYER met2 ;
      RECT 731.330 0.000 731.470 0.420 ;
    END
  END r0_rd_out[70]
  PIN r0_rd_out[71]
    DIRECTION OUTPUT ;
    USE SIGNAL ;
    SHAPE ABUTMENT ;
    PORT
      LAYER met2 ;
      RECT 735.010 0.000 735.150 0.420 ;
    END
  END r0_rd_out[71]
  PIN r0_rd_out[72]
    DIRECTION OUTPUT ;
    USE SIGNAL ;
    SHAPE ABUTMENT ;
    PORT
      LAYER met2 ;
      RECT 738.690 0.000 738.830 0.420 ;
    END
  END r0_rd_out[72]
  PIN r0_rd_out[73]
    DIRECTION OUTPUT ;
    USE SIGNAL ;
    SHAPE ABUTMENT ;
    PORT
      LAYER met2 ;
      RECT 742.370 0.000 742.510 0.420 ;
    END
  END r0_rd_out[73]
  PIN r0_rd_out[74]
    DIRECTION OUTPUT ;
    USE SIGNAL ;
    SHAPE ABUTMENT ;
    PORT
      LAYER met2 ;
      RECT 746.050 0.000 746.190 0.420 ;
    END
  END r0_rd_out[74]
  PIN r0_rd_out[75]
    DIRECTION OUTPUT ;
    USE SIGNAL ;
    SHAPE ABUTMENT ;
    PORT
      LAYER met2 ;
      RECT 749.730 0.000 749.870 0.420 ;
    END
  END r0_rd_out[75]
  PIN r0_rd_out[76]
    DIRECTION OUTPUT ;
    USE SIGNAL ;
    SHAPE ABUTMENT ;
    PORT
      LAYER met2 ;
      RECT 753.410 0.000 753.550 0.420 ;
    END
  END r0_rd_out[76]
  PIN r0_rd_out[77]
    DIRECTION OUTPUT ;
    USE SIGNAL ;
    SHAPE ABUTMENT ;
    PORT
      LAYER met2 ;
      RECT 757.090 0.000 757.230 0.420 ;
    END
  END r0_rd_out[77]
  PIN r0_rd_out[78]
    DIRECTION OUTPUT ;
    USE SIGNAL ;
    SHAPE ABUTMENT ;
    PORT
      LAYER met2 ;
      RECT 760.770 0.000 760.910 0.420 ;
    END
  END r0_rd_out[78]
  PIN r0_rd_out[79]
    DIRECTION OUTPUT ;
    USE SIGNAL ;
    SHAPE ABUTMENT ;
    PORT
      LAYER met2 ;
      RECT 764.450 0.000 764.590 0.420 ;
    END
  END r0_rd_out[79]
  PIN r0_rd_out[80]
    DIRECTION OUTPUT ;
    USE SIGNAL ;
    SHAPE ABUTMENT ;
    PORT
      LAYER met2 ;
      RECT 768.130 0.000 768.270 0.420 ;
    END
  END r0_rd_out[80]
  PIN r0_rd_out[81]
    DIRECTION OUTPUT ;
    USE SIGNAL ;
    SHAPE ABUTMENT ;
    PORT
      LAYER met2 ;
      RECT 771.810 0.000 771.950 0.420 ;
    END
  END r0_rd_out[81]
  PIN r0_rd_out[82]
    DIRECTION OUTPUT ;
    USE SIGNAL ;
    SHAPE ABUTMENT ;
    PORT
      LAYER met2 ;
      RECT 775.490 0.000 775.630 0.420 ;
    END
  END r0_rd_out[82]
  PIN r0_rd_out[83]
    DIRECTION OUTPUT ;
    USE SIGNAL ;
    SHAPE ABUTMENT ;
    PORT
      LAYER met2 ;
      RECT 779.170 0.000 779.310 0.420 ;
    END
  END r0_rd_out[83]
  PIN r0_rd_out[84]
    DIRECTION OUTPUT ;
    USE SIGNAL ;
    SHAPE ABUTMENT ;
    PORT
      LAYER met2 ;
      RECT 782.850 0.000 782.990 0.420 ;
    END
  END r0_rd_out[84]
  PIN r0_rd_out[85]
    DIRECTION OUTPUT ;
    USE SIGNAL ;
    SHAPE ABUTMENT ;
    PORT
      LAYER met2 ;
      RECT 786.530 0.000 786.670 0.420 ;
    END
  END r0_rd_out[85]
  PIN r0_rd_out[86]
    DIRECTION OUTPUT ;
    USE SIGNAL ;
    SHAPE ABUTMENT ;
    PORT
      LAYER met2 ;
      RECT 790.210 0.000 790.350 0.420 ;
    END
  END r0_rd_out[86]
  PIN r0_rd_out[87]
    DIRECTION OUTPUT ;
    USE SIGNAL ;
    SHAPE ABUTMENT ;
    PORT
      LAYER met2 ;
      RECT 793.890 0.000 794.030 0.420 ;
    END
  END r0_rd_out[87]
  PIN r0_rd_out[88]
    DIRECTION OUTPUT ;
    USE SIGNAL ;
    SHAPE ABUTMENT ;
    PORT
      LAYER met2 ;
      RECT 797.570 0.000 797.710 0.420 ;
    END
  END r0_rd_out[88]
  PIN r0_rd_out[89]
    DIRECTION OUTPUT ;
    USE SIGNAL ;
    SHAPE ABUTMENT ;
    PORT
      LAYER met2 ;
      RECT 801.250 0.000 801.390 0.420 ;
    END
  END r0_rd_out[89]
  PIN r0_rd_out[90]
    DIRECTION OUTPUT ;
    USE SIGNAL ;
    SHAPE ABUTMENT ;
    PORT
      LAYER met2 ;
      RECT 804.930 0.000 805.070 0.420 ;
    END
  END r0_rd_out[90]
  PIN r0_rd_out[91]
    DIRECTION OUTPUT ;
    USE SIGNAL ;
    SHAPE ABUTMENT ;
    PORT
      LAYER met2 ;
      RECT 808.610 0.000 808.750 0.420 ;
    END
  END r0_rd_out[91]
  PIN r0_rd_out[92]
    DIRECTION OUTPUT ;
    USE SIGNAL ;
    SHAPE ABUTMENT ;
    PORT
      LAYER met2 ;
      RECT 812.290 0.000 812.430 0.420 ;
    END
  END r0_rd_out[92]
  PIN r0_rd_out[93]
    DIRECTION OUTPUT ;
    USE SIGNAL ;
    SHAPE ABUTMENT ;
    PORT
      LAYER met2 ;
      RECT 815.970 0.000 816.110 0.420 ;
    END
  END r0_rd_out[93]
  PIN r0_rd_out[94]
    DIRECTION OUTPUT ;
    USE SIGNAL ;
    SHAPE ABUTMENT ;
    PORT
      LAYER met2 ;
      RECT 819.650 0.000 819.790 0.420 ;
    END
  END r0_rd_out[94]
  PIN r0_rd_out[95]
    DIRECTION OUTPUT ;
    USE SIGNAL ;
    SHAPE ABUTMENT ;
    PORT
      LAYER met2 ;
      RECT 823.330 0.000 823.470 0.420 ;
    END
  END r0_rd_out[95]
  PIN r0_rd_out[96]
    DIRECTION OUTPUT ;
    USE SIGNAL ;
    SHAPE ABUTMENT ;
    PORT
      LAYER met2 ;
      RECT 827.010 0.000 827.150 0.420 ;
    END
  END r0_rd_out[96]
  PIN r0_rd_out[97]
    DIRECTION OUTPUT ;
    USE SIGNAL ;
    SHAPE ABUTMENT ;
    PORT
      LAYER met2 ;
      RECT 830.690 0.000 830.830 0.420 ;
    END
  END r0_rd_out[97]
  PIN r0_rd_out[98]
    DIRECTION OUTPUT ;
    USE SIGNAL ;
    SHAPE ABUTMENT ;
    PORT
      LAYER met2 ;
      RECT 834.370 0.000 834.510 0.420 ;
    END
  END r0_rd_out[98]
  PIN r0_rd_out[99]
    DIRECTION OUTPUT ;
    USE SIGNAL ;
    SHAPE ABUTMENT ;
    PORT
      LAYER met2 ;
      RECT 838.050 0.000 838.190 0.420 ;
    END
  END r0_rd_out[99]
  PIN r0_rd_out[100]
    DIRECTION OUTPUT ;
    USE SIGNAL ;
    SHAPE ABUTMENT ;
    PORT
      LAYER met2 ;
      RECT 841.730 0.000 841.870 0.420 ;
    END
  END r0_rd_out[100]
  PIN r0_rd_out[101]
    DIRECTION OUTPUT ;
    USE SIGNAL ;
    SHAPE ABUTMENT ;
    PORT
      LAYER met2 ;
      RECT 845.410 0.000 845.550 0.420 ;
    END
  END r0_rd_out[101]
  PIN r0_rd_out[102]
    DIRECTION OUTPUT ;
    USE SIGNAL ;
    SHAPE ABUTMENT ;
    PORT
      LAYER met2 ;
      RECT 849.090 0.000 849.230 0.420 ;
    END
  END r0_rd_out[102]
  PIN r0_rd_out[103]
    DIRECTION OUTPUT ;
    USE SIGNAL ;
    SHAPE ABUTMENT ;
    PORT
      LAYER met2 ;
      RECT 852.770 0.000 852.910 0.420 ;
    END
  END r0_rd_out[103]
  PIN r0_rd_out[104]
    DIRECTION OUTPUT ;
    USE SIGNAL ;
    SHAPE ABUTMENT ;
    PORT
      LAYER met2 ;
      RECT 856.450 0.000 856.590 0.420 ;
    END
  END r0_rd_out[104]
  PIN r0_rd_out[105]
    DIRECTION OUTPUT ;
    USE SIGNAL ;
    SHAPE ABUTMENT ;
    PORT
      LAYER met2 ;
      RECT 860.130 0.000 860.270 0.420 ;
    END
  END r0_rd_out[105]
  PIN r0_rd_out[106]
    DIRECTION OUTPUT ;
    USE SIGNAL ;
    SHAPE ABUTMENT ;
    PORT
      LAYER met2 ;
      RECT 863.810 0.000 863.950 0.420 ;
    END
  END r0_rd_out[106]
  PIN r0_rd_out[107]
    DIRECTION OUTPUT ;
    USE SIGNAL ;
    SHAPE ABUTMENT ;
    PORT
      LAYER met2 ;
      RECT 867.490 0.000 867.630 0.420 ;
    END
  END r0_rd_out[107]
  PIN r0_rd_out[108]
    DIRECTION OUTPUT ;
    USE SIGNAL ;
    SHAPE ABUTMENT ;
    PORT
      LAYER met2 ;
      RECT 871.170 0.000 871.310 0.420 ;
    END
  END r0_rd_out[108]
  PIN r0_rd_out[109]
    DIRECTION OUTPUT ;
    USE SIGNAL ;
    SHAPE ABUTMENT ;
    PORT
      LAYER met2 ;
      RECT 874.850 0.000 874.990 0.420 ;
    END
  END r0_rd_out[109]
  PIN r0_rd_out[110]
    DIRECTION OUTPUT ;
    USE SIGNAL ;
    SHAPE ABUTMENT ;
    PORT
      LAYER met2 ;
      RECT 878.530 0.000 878.670 0.420 ;
    END
  END r0_rd_out[110]
  PIN r0_rd_out[111]
    DIRECTION OUTPUT ;
    USE SIGNAL ;
    SHAPE ABUTMENT ;
    PORT
      LAYER met2 ;
      RECT 882.210 0.000 882.350 0.420 ;
    END
  END r0_rd_out[111]
  PIN r0_rd_out[112]
    DIRECTION OUTPUT ;
    USE SIGNAL ;
    SHAPE ABUTMENT ;
    PORT
      LAYER met2 ;
      RECT 885.890 0.000 886.030 0.420 ;
    END
  END r0_rd_out[112]
  PIN r0_rd_out[113]
    DIRECTION OUTPUT ;
    USE SIGNAL ;
    SHAPE ABUTMENT ;
    PORT
      LAYER met2 ;
      RECT 889.570 0.000 889.710 0.420 ;
    END
  END r0_rd_out[113]
  PIN r0_rd_out[114]
    DIRECTION OUTPUT ;
    USE SIGNAL ;
    SHAPE ABUTMENT ;
    PORT
      LAYER met2 ;
      RECT 893.250 0.000 893.390 0.420 ;
    END
  END r0_rd_out[114]
  PIN r0_rd_out[115]
    DIRECTION OUTPUT ;
    USE SIGNAL ;
    SHAPE ABUTMENT ;
    PORT
      LAYER met2 ;
      RECT 896.930 0.000 897.070 0.420 ;
    END
  END r0_rd_out[115]
  PIN r0_rd_out[116]
    DIRECTION OUTPUT ;
    USE SIGNAL ;
    SHAPE ABUTMENT ;
    PORT
      LAYER met2 ;
      RECT 900.610 0.000 900.750 0.420 ;
    END
  END r0_rd_out[116]
  PIN r0_rd_out[117]
    DIRECTION OUTPUT ;
    USE SIGNAL ;
    SHAPE ABUTMENT ;
    PORT
      LAYER met2 ;
      RECT 904.290 0.000 904.430 0.420 ;
    END
  END r0_rd_out[117]
  PIN r0_rd_out[118]
    DIRECTION OUTPUT ;
    USE SIGNAL ;
    SHAPE ABUTMENT ;
    PORT
      LAYER met2 ;
      RECT 907.970 0.000 908.110 0.420 ;
    END
  END r0_rd_out[118]
  PIN r0_rd_out[119]
    DIRECTION OUTPUT ;
    USE SIGNAL ;
    SHAPE ABUTMENT ;
    PORT
      LAYER met2 ;
      RECT 911.650 0.000 911.790 0.420 ;
    END
  END r0_rd_out[119]
  PIN r0_rd_out[120]
    DIRECTION OUTPUT ;
    USE SIGNAL ;
    SHAPE ABUTMENT ;
    PORT
      LAYER met2 ;
      RECT 915.330 0.000 915.470 0.420 ;
    END
  END r0_rd_out[120]
  PIN r0_rd_out[121]
    DIRECTION OUTPUT ;
    USE SIGNAL ;
    SHAPE ABUTMENT ;
    PORT
      LAYER met2 ;
      RECT 919.010 0.000 919.150 0.420 ;
    END
  END r0_rd_out[121]
  PIN r0_rd_out[122]
    DIRECTION OUTPUT ;
    USE SIGNAL ;
    SHAPE ABUTMENT ;
    PORT
      LAYER met2 ;
      RECT 922.690 0.000 922.830 0.420 ;
    END
  END r0_rd_out[122]
  PIN r0_rd_out[123]
    DIRECTION OUTPUT ;
    USE SIGNAL ;
    SHAPE ABUTMENT ;
    PORT
      LAYER met2 ;
      RECT 926.370 0.000 926.510 0.420 ;
    END
  END r0_rd_out[123]
  PIN r0_rd_out[124]
    DIRECTION OUTPUT ;
    USE SIGNAL ;
    SHAPE ABUTMENT ;
    PORT
      LAYER met2 ;
      RECT 930.050 0.000 930.190 0.420 ;
    END
  END r0_rd_out[124]
  PIN r0_rd_out[125]
    DIRECTION OUTPUT ;
    USE SIGNAL ;
    SHAPE ABUTMENT ;
    PORT
      LAYER met2 ;
      RECT 933.730 0.000 933.870 0.420 ;
    END
  END r0_rd_out[125]
  PIN r0_rd_out[126]
    DIRECTION OUTPUT ;
    USE SIGNAL ;
    SHAPE ABUTMENT ;
    PORT
      LAYER met2 ;
      RECT 937.410 0.000 937.550 0.420 ;
    END
  END r0_rd_out[126]
  PIN r0_rd_out[127]
    DIRECTION OUTPUT ;
    USE SIGNAL ;
    SHAPE ABUTMENT ;
    PORT
      LAYER met2 ;
      RECT 941.090 0.000 941.230 0.420 ;
    END
  END r0_rd_out[127]
  PIN r0_rd_out[128]
    DIRECTION OUTPUT ;
    USE SIGNAL ;
    SHAPE ABUTMENT ;
    PORT
      LAYER met2 ;
      RECT 2.690 1571.740 2.830 1572.160 ;
    END
  END r0_rd_out[128]
  PIN r0_rd_out[129]
    DIRECTION OUTPUT ;
    USE SIGNAL ;
    SHAPE ABUTMENT ;
    PORT
      LAYER met2 ;
      RECT 10.050 1571.740 10.190 1572.160 ;
    END
  END r0_rd_out[129]
  PIN r0_rd_out[130]
    DIRECTION OUTPUT ;
    USE SIGNAL ;
    SHAPE ABUTMENT ;
    PORT
      LAYER met2 ;
      RECT 17.410 1571.740 17.550 1572.160 ;
    END
  END r0_rd_out[130]
  PIN r0_rd_out[131]
    DIRECTION OUTPUT ;
    USE SIGNAL ;
    SHAPE ABUTMENT ;
    PORT
      LAYER met2 ;
      RECT 24.770 1571.740 24.910 1572.160 ;
    END
  END r0_rd_out[131]
  PIN r0_rd_out[132]
    DIRECTION OUTPUT ;
    USE SIGNAL ;
    SHAPE ABUTMENT ;
    PORT
      LAYER met2 ;
      RECT 32.130 1571.740 32.270 1572.160 ;
    END
  END r0_rd_out[132]
  PIN r0_rd_out[133]
    DIRECTION OUTPUT ;
    USE SIGNAL ;
    SHAPE ABUTMENT ;
    PORT
      LAYER met2 ;
      RECT 39.490 1571.740 39.630 1572.160 ;
    END
  END r0_rd_out[133]
  PIN r0_rd_out[134]
    DIRECTION OUTPUT ;
    USE SIGNAL ;
    SHAPE ABUTMENT ;
    PORT
      LAYER met2 ;
      RECT 46.850 1571.740 46.990 1572.160 ;
    END
  END r0_rd_out[134]
  PIN r0_rd_out[135]
    DIRECTION OUTPUT ;
    USE SIGNAL ;
    SHAPE ABUTMENT ;
    PORT
      LAYER met2 ;
      RECT 54.210 1571.740 54.350 1572.160 ;
    END
  END r0_rd_out[135]
  PIN r0_rd_out[136]
    DIRECTION OUTPUT ;
    USE SIGNAL ;
    SHAPE ABUTMENT ;
    PORT
      LAYER met2 ;
      RECT 61.570 1571.740 61.710 1572.160 ;
    END
  END r0_rd_out[136]
  PIN r0_rd_out[137]
    DIRECTION OUTPUT ;
    USE SIGNAL ;
    SHAPE ABUTMENT ;
    PORT
      LAYER met2 ;
      RECT 68.930 1571.740 69.070 1572.160 ;
    END
  END r0_rd_out[137]
  PIN r0_rd_out[138]
    DIRECTION OUTPUT ;
    USE SIGNAL ;
    SHAPE ABUTMENT ;
    PORT
      LAYER met2 ;
      RECT 76.290 1571.740 76.430 1572.160 ;
    END
  END r0_rd_out[138]
  PIN r0_rd_out[139]
    DIRECTION OUTPUT ;
    USE SIGNAL ;
    SHAPE ABUTMENT ;
    PORT
      LAYER met2 ;
      RECT 83.650 1571.740 83.790 1572.160 ;
    END
  END r0_rd_out[139]
  PIN r0_rd_out[140]
    DIRECTION OUTPUT ;
    USE SIGNAL ;
    SHAPE ABUTMENT ;
    PORT
      LAYER met2 ;
      RECT 91.010 1571.740 91.150 1572.160 ;
    END
  END r0_rd_out[140]
  PIN r0_rd_out[141]
    DIRECTION OUTPUT ;
    USE SIGNAL ;
    SHAPE ABUTMENT ;
    PORT
      LAYER met2 ;
      RECT 98.370 1571.740 98.510 1572.160 ;
    END
  END r0_rd_out[141]
  PIN r0_rd_out[142]
    DIRECTION OUTPUT ;
    USE SIGNAL ;
    SHAPE ABUTMENT ;
    PORT
      LAYER met2 ;
      RECT 105.730 1571.740 105.870 1572.160 ;
    END
  END r0_rd_out[142]
  PIN r0_rd_out[143]
    DIRECTION OUTPUT ;
    USE SIGNAL ;
    SHAPE ABUTMENT ;
    PORT
      LAYER met2 ;
      RECT 113.090 1571.740 113.230 1572.160 ;
    END
  END r0_rd_out[143]
  PIN r0_rd_out[144]
    DIRECTION OUTPUT ;
    USE SIGNAL ;
    SHAPE ABUTMENT ;
    PORT
      LAYER met2 ;
      RECT 120.450 1571.740 120.590 1572.160 ;
    END
  END r0_rd_out[144]
  PIN r0_rd_out[145]
    DIRECTION OUTPUT ;
    USE SIGNAL ;
    SHAPE ABUTMENT ;
    PORT
      LAYER met2 ;
      RECT 127.810 1571.740 127.950 1572.160 ;
    END
  END r0_rd_out[145]
  PIN r0_rd_out[146]
    DIRECTION OUTPUT ;
    USE SIGNAL ;
    SHAPE ABUTMENT ;
    PORT
      LAYER met2 ;
      RECT 135.170 1571.740 135.310 1572.160 ;
    END
  END r0_rd_out[146]
  PIN r0_rd_out[147]
    DIRECTION OUTPUT ;
    USE SIGNAL ;
    SHAPE ABUTMENT ;
    PORT
      LAYER met2 ;
      RECT 142.530 1571.740 142.670 1572.160 ;
    END
  END r0_rd_out[147]
  PIN r0_rd_out[148]
    DIRECTION OUTPUT ;
    USE SIGNAL ;
    SHAPE ABUTMENT ;
    PORT
      LAYER met2 ;
      RECT 149.890 1571.740 150.030 1572.160 ;
    END
  END r0_rd_out[148]
  PIN r0_rd_out[149]
    DIRECTION OUTPUT ;
    USE SIGNAL ;
    SHAPE ABUTMENT ;
    PORT
      LAYER met2 ;
      RECT 157.250 1571.740 157.390 1572.160 ;
    END
  END r0_rd_out[149]
  PIN r0_rd_out[150]
    DIRECTION OUTPUT ;
    USE SIGNAL ;
    SHAPE ABUTMENT ;
    PORT
      LAYER met2 ;
      RECT 164.610 1571.740 164.750 1572.160 ;
    END
  END r0_rd_out[150]
  PIN r0_rd_out[151]
    DIRECTION OUTPUT ;
    USE SIGNAL ;
    SHAPE ABUTMENT ;
    PORT
      LAYER met2 ;
      RECT 171.970 1571.740 172.110 1572.160 ;
    END
  END r0_rd_out[151]
  PIN r0_rd_out[152]
    DIRECTION OUTPUT ;
    USE SIGNAL ;
    SHAPE ABUTMENT ;
    PORT
      LAYER met2 ;
      RECT 179.330 1571.740 179.470 1572.160 ;
    END
  END r0_rd_out[152]
  PIN r0_rd_out[153]
    DIRECTION OUTPUT ;
    USE SIGNAL ;
    SHAPE ABUTMENT ;
    PORT
      LAYER met2 ;
      RECT 186.690 1571.740 186.830 1572.160 ;
    END
  END r0_rd_out[153]
  PIN r0_rd_out[154]
    DIRECTION OUTPUT ;
    USE SIGNAL ;
    SHAPE ABUTMENT ;
    PORT
      LAYER met2 ;
      RECT 194.050 1571.740 194.190 1572.160 ;
    END
  END r0_rd_out[154]
  PIN r0_rd_out[155]
    DIRECTION OUTPUT ;
    USE SIGNAL ;
    SHAPE ABUTMENT ;
    PORT
      LAYER met2 ;
      RECT 201.410 1571.740 201.550 1572.160 ;
    END
  END r0_rd_out[155]
  PIN r0_rd_out[156]
    DIRECTION OUTPUT ;
    USE SIGNAL ;
    SHAPE ABUTMENT ;
    PORT
      LAYER met2 ;
      RECT 208.770 1571.740 208.910 1572.160 ;
    END
  END r0_rd_out[156]
  PIN r0_rd_out[157]
    DIRECTION OUTPUT ;
    USE SIGNAL ;
    SHAPE ABUTMENT ;
    PORT
      LAYER met2 ;
      RECT 216.130 1571.740 216.270 1572.160 ;
    END
  END r0_rd_out[157]
  PIN r0_rd_out[158]
    DIRECTION OUTPUT ;
    USE SIGNAL ;
    SHAPE ABUTMENT ;
    PORT
      LAYER met2 ;
      RECT 223.490 1571.740 223.630 1572.160 ;
    END
  END r0_rd_out[158]
  PIN r0_rd_out[159]
    DIRECTION OUTPUT ;
    USE SIGNAL ;
    SHAPE ABUTMENT ;
    PORT
      LAYER met2 ;
      RECT 230.850 1571.740 230.990 1572.160 ;
    END
  END r0_rd_out[159]
  PIN r0_rd_out[160]
    DIRECTION OUTPUT ;
    USE SIGNAL ;
    SHAPE ABUTMENT ;
    PORT
      LAYER met2 ;
      RECT 238.210 1571.740 238.350 1572.160 ;
    END
  END r0_rd_out[160]
  PIN r0_rd_out[161]
    DIRECTION OUTPUT ;
    USE SIGNAL ;
    SHAPE ABUTMENT ;
    PORT
      LAYER met2 ;
      RECT 245.570 1571.740 245.710 1572.160 ;
    END
  END r0_rd_out[161]
  PIN r0_rd_out[162]
    DIRECTION OUTPUT ;
    USE SIGNAL ;
    SHAPE ABUTMENT ;
    PORT
      LAYER met2 ;
      RECT 252.930 1571.740 253.070 1572.160 ;
    END
  END r0_rd_out[162]
  PIN r0_rd_out[163]
    DIRECTION OUTPUT ;
    USE SIGNAL ;
    SHAPE ABUTMENT ;
    PORT
      LAYER met2 ;
      RECT 260.290 1571.740 260.430 1572.160 ;
    END
  END r0_rd_out[163]
  PIN r0_rd_out[164]
    DIRECTION OUTPUT ;
    USE SIGNAL ;
    SHAPE ABUTMENT ;
    PORT
      LAYER met2 ;
      RECT 267.650 1571.740 267.790 1572.160 ;
    END
  END r0_rd_out[164]
  PIN r0_rd_out[165]
    DIRECTION OUTPUT ;
    USE SIGNAL ;
    SHAPE ABUTMENT ;
    PORT
      LAYER met2 ;
      RECT 275.010 1571.740 275.150 1572.160 ;
    END
  END r0_rd_out[165]
  PIN r0_rd_out[166]
    DIRECTION OUTPUT ;
    USE SIGNAL ;
    SHAPE ABUTMENT ;
    PORT
      LAYER met2 ;
      RECT 282.370 1571.740 282.510 1572.160 ;
    END
  END r0_rd_out[166]
  PIN r0_rd_out[167]
    DIRECTION OUTPUT ;
    USE SIGNAL ;
    SHAPE ABUTMENT ;
    PORT
      LAYER met2 ;
      RECT 289.730 1571.740 289.870 1572.160 ;
    END
  END r0_rd_out[167]
  PIN r0_rd_out[168]
    DIRECTION OUTPUT ;
    USE SIGNAL ;
    SHAPE ABUTMENT ;
    PORT
      LAYER met2 ;
      RECT 297.090 1571.740 297.230 1572.160 ;
    END
  END r0_rd_out[168]
  PIN r0_rd_out[169]
    DIRECTION OUTPUT ;
    USE SIGNAL ;
    SHAPE ABUTMENT ;
    PORT
      LAYER met2 ;
      RECT 304.450 1571.740 304.590 1572.160 ;
    END
  END r0_rd_out[169]
  PIN r0_rd_out[170]
    DIRECTION OUTPUT ;
    USE SIGNAL ;
    SHAPE ABUTMENT ;
    PORT
      LAYER met2 ;
      RECT 311.810 1571.740 311.950 1572.160 ;
    END
  END r0_rd_out[170]
  PIN r0_rd_out[171]
    DIRECTION OUTPUT ;
    USE SIGNAL ;
    SHAPE ABUTMENT ;
    PORT
      LAYER met2 ;
      RECT 319.170 1571.740 319.310 1572.160 ;
    END
  END r0_rd_out[171]
  PIN r0_rd_out[172]
    DIRECTION OUTPUT ;
    USE SIGNAL ;
    SHAPE ABUTMENT ;
    PORT
      LAYER met2 ;
      RECT 326.530 1571.740 326.670 1572.160 ;
    END
  END r0_rd_out[172]
  PIN r0_rd_out[173]
    DIRECTION OUTPUT ;
    USE SIGNAL ;
    SHAPE ABUTMENT ;
    PORT
      LAYER met2 ;
      RECT 333.890 1571.740 334.030 1572.160 ;
    END
  END r0_rd_out[173]
  PIN r0_rd_out[174]
    DIRECTION OUTPUT ;
    USE SIGNAL ;
    SHAPE ABUTMENT ;
    PORT
      LAYER met2 ;
      RECT 341.250 1571.740 341.390 1572.160 ;
    END
  END r0_rd_out[174]
  PIN r0_rd_out[175]
    DIRECTION OUTPUT ;
    USE SIGNAL ;
    SHAPE ABUTMENT ;
    PORT
      LAYER met2 ;
      RECT 348.610 1571.740 348.750 1572.160 ;
    END
  END r0_rd_out[175]
  PIN r0_rd_out[176]
    DIRECTION OUTPUT ;
    USE SIGNAL ;
    SHAPE ABUTMENT ;
    PORT
      LAYER met2 ;
      RECT 355.970 1571.740 356.110 1572.160 ;
    END
  END r0_rd_out[176]
  PIN r0_rd_out[177]
    DIRECTION OUTPUT ;
    USE SIGNAL ;
    SHAPE ABUTMENT ;
    PORT
      LAYER met2 ;
      RECT 363.330 1571.740 363.470 1572.160 ;
    END
  END r0_rd_out[177]
  PIN r0_rd_out[178]
    DIRECTION OUTPUT ;
    USE SIGNAL ;
    SHAPE ABUTMENT ;
    PORT
      LAYER met2 ;
      RECT 370.690 1571.740 370.830 1572.160 ;
    END
  END r0_rd_out[178]
  PIN r0_rd_out[179]
    DIRECTION OUTPUT ;
    USE SIGNAL ;
    SHAPE ABUTMENT ;
    PORT
      LAYER met2 ;
      RECT 378.050 1571.740 378.190 1572.160 ;
    END
  END r0_rd_out[179]
  PIN r0_rd_out[180]
    DIRECTION OUTPUT ;
    USE SIGNAL ;
    SHAPE ABUTMENT ;
    PORT
      LAYER met2 ;
      RECT 385.410 1571.740 385.550 1572.160 ;
    END
  END r0_rd_out[180]
  PIN r0_rd_out[181]
    DIRECTION OUTPUT ;
    USE SIGNAL ;
    SHAPE ABUTMENT ;
    PORT
      LAYER met2 ;
      RECT 392.770 1571.740 392.910 1572.160 ;
    END
  END r0_rd_out[181]
  PIN r0_rd_out[182]
    DIRECTION OUTPUT ;
    USE SIGNAL ;
    SHAPE ABUTMENT ;
    PORT
      LAYER met2 ;
      RECT 400.130 1571.740 400.270 1572.160 ;
    END
  END r0_rd_out[182]
  PIN r0_rd_out[183]
    DIRECTION OUTPUT ;
    USE SIGNAL ;
    SHAPE ABUTMENT ;
    PORT
      LAYER met2 ;
      RECT 407.490 1571.740 407.630 1572.160 ;
    END
  END r0_rd_out[183]
  PIN r0_rd_out[184]
    DIRECTION OUTPUT ;
    USE SIGNAL ;
    SHAPE ABUTMENT ;
    PORT
      LAYER met2 ;
      RECT 414.850 1571.740 414.990 1572.160 ;
    END
  END r0_rd_out[184]
  PIN r0_rd_out[185]
    DIRECTION OUTPUT ;
    USE SIGNAL ;
    SHAPE ABUTMENT ;
    PORT
      LAYER met2 ;
      RECT 422.210 1571.740 422.350 1572.160 ;
    END
  END r0_rd_out[185]
  PIN r0_rd_out[186]
    DIRECTION OUTPUT ;
    USE SIGNAL ;
    SHAPE ABUTMENT ;
    PORT
      LAYER met2 ;
      RECT 429.570 1571.740 429.710 1572.160 ;
    END
  END r0_rd_out[186]
  PIN r0_rd_out[187]
    DIRECTION OUTPUT ;
    USE SIGNAL ;
    SHAPE ABUTMENT ;
    PORT
      LAYER met2 ;
      RECT 436.930 1571.740 437.070 1572.160 ;
    END
  END r0_rd_out[187]
  PIN r0_rd_out[188]
    DIRECTION OUTPUT ;
    USE SIGNAL ;
    SHAPE ABUTMENT ;
    PORT
      LAYER met2 ;
      RECT 444.290 1571.740 444.430 1572.160 ;
    END
  END r0_rd_out[188]
  PIN r0_rd_out[189]
    DIRECTION OUTPUT ;
    USE SIGNAL ;
    SHAPE ABUTMENT ;
    PORT
      LAYER met2 ;
      RECT 451.650 1571.740 451.790 1572.160 ;
    END
  END r0_rd_out[189]
  PIN r0_rd_out[190]
    DIRECTION OUTPUT ;
    USE SIGNAL ;
    SHAPE ABUTMENT ;
    PORT
      LAYER met2 ;
      RECT 459.010 1571.740 459.150 1572.160 ;
    END
  END r0_rd_out[190]
  PIN r0_rd_out[191]
    DIRECTION OUTPUT ;
    USE SIGNAL ;
    SHAPE ABUTMENT ;
    PORT
      LAYER met2 ;
      RECT 466.370 1571.740 466.510 1572.160 ;
    END
  END r0_rd_out[191]
  PIN r0_rd_out[192]
    DIRECTION OUTPUT ;
    USE SIGNAL ;
    SHAPE ABUTMENT ;
    PORT
      LAYER met2 ;
      RECT 473.730 1571.740 473.870 1572.160 ;
    END
  END r0_rd_out[192]
  PIN r0_rd_out[193]
    DIRECTION OUTPUT ;
    USE SIGNAL ;
    SHAPE ABUTMENT ;
    PORT
      LAYER met2 ;
      RECT 481.090 1571.740 481.230 1572.160 ;
    END
  END r0_rd_out[193]
  PIN r0_rd_out[194]
    DIRECTION OUTPUT ;
    USE SIGNAL ;
    SHAPE ABUTMENT ;
    PORT
      LAYER met2 ;
      RECT 488.450 1571.740 488.590 1572.160 ;
    END
  END r0_rd_out[194]
  PIN r0_rd_out[195]
    DIRECTION OUTPUT ;
    USE SIGNAL ;
    SHAPE ABUTMENT ;
    PORT
      LAYER met2 ;
      RECT 495.810 1571.740 495.950 1572.160 ;
    END
  END r0_rd_out[195]
  PIN r0_rd_out[196]
    DIRECTION OUTPUT ;
    USE SIGNAL ;
    SHAPE ABUTMENT ;
    PORT
      LAYER met2 ;
      RECT 503.170 1571.740 503.310 1572.160 ;
    END
  END r0_rd_out[196]
  PIN r0_rd_out[197]
    DIRECTION OUTPUT ;
    USE SIGNAL ;
    SHAPE ABUTMENT ;
    PORT
      LAYER met2 ;
      RECT 510.530 1571.740 510.670 1572.160 ;
    END
  END r0_rd_out[197]
  PIN r0_rd_out[198]
    DIRECTION OUTPUT ;
    USE SIGNAL ;
    SHAPE ABUTMENT ;
    PORT
      LAYER met2 ;
      RECT 517.890 1571.740 518.030 1572.160 ;
    END
  END r0_rd_out[198]
  PIN r0_rd_out[199]
    DIRECTION OUTPUT ;
    USE SIGNAL ;
    SHAPE ABUTMENT ;
    PORT
      LAYER met2 ;
      RECT 525.250 1571.740 525.390 1572.160 ;
    END
  END r0_rd_out[199]
  PIN r0_rd_out[200]
    DIRECTION OUTPUT ;
    USE SIGNAL ;
    SHAPE ABUTMENT ;
    PORT
      LAYER met2 ;
      RECT 532.610 1571.740 532.750 1572.160 ;
    END
  END r0_rd_out[200]
  PIN r0_rd_out[201]
    DIRECTION OUTPUT ;
    USE SIGNAL ;
    SHAPE ABUTMENT ;
    PORT
      LAYER met2 ;
      RECT 539.970 1571.740 540.110 1572.160 ;
    END
  END r0_rd_out[201]
  PIN r0_rd_out[202]
    DIRECTION OUTPUT ;
    USE SIGNAL ;
    SHAPE ABUTMENT ;
    PORT
      LAYER met2 ;
      RECT 547.330 1571.740 547.470 1572.160 ;
    END
  END r0_rd_out[202]
  PIN r0_rd_out[203]
    DIRECTION OUTPUT ;
    USE SIGNAL ;
    SHAPE ABUTMENT ;
    PORT
      LAYER met2 ;
      RECT 554.690 1571.740 554.830 1572.160 ;
    END
  END r0_rd_out[203]
  PIN r0_rd_out[204]
    DIRECTION OUTPUT ;
    USE SIGNAL ;
    SHAPE ABUTMENT ;
    PORT
      LAYER met2 ;
      RECT 562.050 1571.740 562.190 1572.160 ;
    END
  END r0_rd_out[204]
  PIN r0_rd_out[205]
    DIRECTION OUTPUT ;
    USE SIGNAL ;
    SHAPE ABUTMENT ;
    PORT
      LAYER met2 ;
      RECT 569.410 1571.740 569.550 1572.160 ;
    END
  END r0_rd_out[205]
  PIN r0_rd_out[206]
    DIRECTION OUTPUT ;
    USE SIGNAL ;
    SHAPE ABUTMENT ;
    PORT
      LAYER met2 ;
      RECT 576.770 1571.740 576.910 1572.160 ;
    END
  END r0_rd_out[206]
  PIN r0_rd_out[207]
    DIRECTION OUTPUT ;
    USE SIGNAL ;
    SHAPE ABUTMENT ;
    PORT
      LAYER met2 ;
      RECT 584.130 1571.740 584.270 1572.160 ;
    END
  END r0_rd_out[207]
  PIN r0_rd_out[208]
    DIRECTION OUTPUT ;
    USE SIGNAL ;
    SHAPE ABUTMENT ;
    PORT
      LAYER met2 ;
      RECT 591.490 1571.740 591.630 1572.160 ;
    END
  END r0_rd_out[208]
  PIN r0_rd_out[209]
    DIRECTION OUTPUT ;
    USE SIGNAL ;
    SHAPE ABUTMENT ;
    PORT
      LAYER met2 ;
      RECT 598.850 1571.740 598.990 1572.160 ;
    END
  END r0_rd_out[209]
  PIN r0_rd_out[210]
    DIRECTION OUTPUT ;
    USE SIGNAL ;
    SHAPE ABUTMENT ;
    PORT
      LAYER met2 ;
      RECT 606.210 1571.740 606.350 1572.160 ;
    END
  END r0_rd_out[210]
  PIN r0_rd_out[211]
    DIRECTION OUTPUT ;
    USE SIGNAL ;
    SHAPE ABUTMENT ;
    PORT
      LAYER met2 ;
      RECT 613.570 1571.740 613.710 1572.160 ;
    END
  END r0_rd_out[211]
  PIN r0_rd_out[212]
    DIRECTION OUTPUT ;
    USE SIGNAL ;
    SHAPE ABUTMENT ;
    PORT
      LAYER met2 ;
      RECT 620.930 1571.740 621.070 1572.160 ;
    END
  END r0_rd_out[212]
  PIN r0_rd_out[213]
    DIRECTION OUTPUT ;
    USE SIGNAL ;
    SHAPE ABUTMENT ;
    PORT
      LAYER met2 ;
      RECT 628.290 1571.740 628.430 1572.160 ;
    END
  END r0_rd_out[213]
  PIN r0_rd_out[214]
    DIRECTION OUTPUT ;
    USE SIGNAL ;
    SHAPE ABUTMENT ;
    PORT
      LAYER met2 ;
      RECT 635.650 1571.740 635.790 1572.160 ;
    END
  END r0_rd_out[214]
  PIN r0_rd_out[215]
    DIRECTION OUTPUT ;
    USE SIGNAL ;
    SHAPE ABUTMENT ;
    PORT
      LAYER met2 ;
      RECT 643.010 1571.740 643.150 1572.160 ;
    END
  END r0_rd_out[215]
  PIN r0_rd_out[216]
    DIRECTION OUTPUT ;
    USE SIGNAL ;
    SHAPE ABUTMENT ;
    PORT
      LAYER met2 ;
      RECT 650.370 1571.740 650.510 1572.160 ;
    END
  END r0_rd_out[216]
  PIN r0_rd_out[217]
    DIRECTION OUTPUT ;
    USE SIGNAL ;
    SHAPE ABUTMENT ;
    PORT
      LAYER met2 ;
      RECT 657.730 1571.740 657.870 1572.160 ;
    END
  END r0_rd_out[217]
  PIN r0_rd_out[218]
    DIRECTION OUTPUT ;
    USE SIGNAL ;
    SHAPE ABUTMENT ;
    PORT
      LAYER met2 ;
      RECT 665.090 1571.740 665.230 1572.160 ;
    END
  END r0_rd_out[218]
  PIN r0_rd_out[219]
    DIRECTION OUTPUT ;
    USE SIGNAL ;
    SHAPE ABUTMENT ;
    PORT
      LAYER met2 ;
      RECT 672.450 1571.740 672.590 1572.160 ;
    END
  END r0_rd_out[219]
  PIN r0_rd_out[220]
    DIRECTION OUTPUT ;
    USE SIGNAL ;
    SHAPE ABUTMENT ;
    PORT
      LAYER met2 ;
      RECT 679.810 1571.740 679.950 1572.160 ;
    END
  END r0_rd_out[220]
  PIN r0_rd_out[221]
    DIRECTION OUTPUT ;
    USE SIGNAL ;
    SHAPE ABUTMENT ;
    PORT
      LAYER met2 ;
      RECT 687.170 1571.740 687.310 1572.160 ;
    END
  END r0_rd_out[221]
  PIN r0_rd_out[222]
    DIRECTION OUTPUT ;
    USE SIGNAL ;
    SHAPE ABUTMENT ;
    PORT
      LAYER met2 ;
      RECT 694.530 1571.740 694.670 1572.160 ;
    END
  END r0_rd_out[222]
  PIN r0_rd_out[223]
    DIRECTION OUTPUT ;
    USE SIGNAL ;
    SHAPE ABUTMENT ;
    PORT
      LAYER met2 ;
      RECT 701.890 1571.740 702.030 1572.160 ;
    END
  END r0_rd_out[223]
  PIN r0_rd_out[224]
    DIRECTION OUTPUT ;
    USE SIGNAL ;
    SHAPE ABUTMENT ;
    PORT
      LAYER met2 ;
      RECT 709.250 1571.740 709.390 1572.160 ;
    END
  END r0_rd_out[224]
  PIN r0_rd_out[225]
    DIRECTION OUTPUT ;
    USE SIGNAL ;
    SHAPE ABUTMENT ;
    PORT
      LAYER met2 ;
      RECT 716.610 1571.740 716.750 1572.160 ;
    END
  END r0_rd_out[225]
  PIN r0_rd_out[226]
    DIRECTION OUTPUT ;
    USE SIGNAL ;
    SHAPE ABUTMENT ;
    PORT
      LAYER met2 ;
      RECT 723.970 1571.740 724.110 1572.160 ;
    END
  END r0_rd_out[226]
  PIN r0_rd_out[227]
    DIRECTION OUTPUT ;
    USE SIGNAL ;
    SHAPE ABUTMENT ;
    PORT
      LAYER met2 ;
      RECT 731.330 1571.740 731.470 1572.160 ;
    END
  END r0_rd_out[227]
  PIN r0_rd_out[228]
    DIRECTION OUTPUT ;
    USE SIGNAL ;
    SHAPE ABUTMENT ;
    PORT
      LAYER met2 ;
      RECT 738.690 1571.740 738.830 1572.160 ;
    END
  END r0_rd_out[228]
  PIN r0_rd_out[229]
    DIRECTION OUTPUT ;
    USE SIGNAL ;
    SHAPE ABUTMENT ;
    PORT
      LAYER met2 ;
      RECT 746.050 1571.740 746.190 1572.160 ;
    END
  END r0_rd_out[229]
  PIN r0_rd_out[230]
    DIRECTION OUTPUT ;
    USE SIGNAL ;
    SHAPE ABUTMENT ;
    PORT
      LAYER met2 ;
      RECT 753.410 1571.740 753.550 1572.160 ;
    END
  END r0_rd_out[230]
  PIN r0_rd_out[231]
    DIRECTION OUTPUT ;
    USE SIGNAL ;
    SHAPE ABUTMENT ;
    PORT
      LAYER met2 ;
      RECT 760.770 1571.740 760.910 1572.160 ;
    END
  END r0_rd_out[231]
  PIN r0_rd_out[232]
    DIRECTION OUTPUT ;
    USE SIGNAL ;
    SHAPE ABUTMENT ;
    PORT
      LAYER met2 ;
      RECT 768.130 1571.740 768.270 1572.160 ;
    END
  END r0_rd_out[232]
  PIN r0_rd_out[233]
    DIRECTION OUTPUT ;
    USE SIGNAL ;
    SHAPE ABUTMENT ;
    PORT
      LAYER met2 ;
      RECT 775.490 1571.740 775.630 1572.160 ;
    END
  END r0_rd_out[233]
  PIN r0_rd_out[234]
    DIRECTION OUTPUT ;
    USE SIGNAL ;
    SHAPE ABUTMENT ;
    PORT
      LAYER met2 ;
      RECT 782.850 1571.740 782.990 1572.160 ;
    END
  END r0_rd_out[234]
  PIN r0_rd_out[235]
    DIRECTION OUTPUT ;
    USE SIGNAL ;
    SHAPE ABUTMENT ;
    PORT
      LAYER met2 ;
      RECT 790.210 1571.740 790.350 1572.160 ;
    END
  END r0_rd_out[235]
  PIN r0_rd_out[236]
    DIRECTION OUTPUT ;
    USE SIGNAL ;
    SHAPE ABUTMENT ;
    PORT
      LAYER met2 ;
      RECT 797.570 1571.740 797.710 1572.160 ;
    END
  END r0_rd_out[236]
  PIN r0_rd_out[237]
    DIRECTION OUTPUT ;
    USE SIGNAL ;
    SHAPE ABUTMENT ;
    PORT
      LAYER met2 ;
      RECT 804.930 1571.740 805.070 1572.160 ;
    END
  END r0_rd_out[237]
  PIN r0_rd_out[238]
    DIRECTION OUTPUT ;
    USE SIGNAL ;
    SHAPE ABUTMENT ;
    PORT
      LAYER met2 ;
      RECT 812.290 1571.740 812.430 1572.160 ;
    END
  END r0_rd_out[238]
  PIN r0_rd_out[239]
    DIRECTION OUTPUT ;
    USE SIGNAL ;
    SHAPE ABUTMENT ;
    PORT
      LAYER met2 ;
      RECT 819.650 1571.740 819.790 1572.160 ;
    END
  END r0_rd_out[239]
  PIN r0_rd_out[240]
    DIRECTION OUTPUT ;
    USE SIGNAL ;
    SHAPE ABUTMENT ;
    PORT
      LAYER met2 ;
      RECT 827.010 1571.740 827.150 1572.160 ;
    END
  END r0_rd_out[240]
  PIN r0_rd_out[241]
    DIRECTION OUTPUT ;
    USE SIGNAL ;
    SHAPE ABUTMENT ;
    PORT
      LAYER met2 ;
      RECT 834.370 1571.740 834.510 1572.160 ;
    END
  END r0_rd_out[241]
  PIN r0_rd_out[242]
    DIRECTION OUTPUT ;
    USE SIGNAL ;
    SHAPE ABUTMENT ;
    PORT
      LAYER met2 ;
      RECT 841.730 1571.740 841.870 1572.160 ;
    END
  END r0_rd_out[242]
  PIN r0_rd_out[243]
    DIRECTION OUTPUT ;
    USE SIGNAL ;
    SHAPE ABUTMENT ;
    PORT
      LAYER met2 ;
      RECT 849.090 1571.740 849.230 1572.160 ;
    END
  END r0_rd_out[243]
  PIN r0_rd_out[244]
    DIRECTION OUTPUT ;
    USE SIGNAL ;
    SHAPE ABUTMENT ;
    PORT
      LAYER met2 ;
      RECT 856.450 1571.740 856.590 1572.160 ;
    END
  END r0_rd_out[244]
  PIN r0_rd_out[245]
    DIRECTION OUTPUT ;
    USE SIGNAL ;
    SHAPE ABUTMENT ;
    PORT
      LAYER met2 ;
      RECT 863.810 1571.740 863.950 1572.160 ;
    END
  END r0_rd_out[245]
  PIN r0_rd_out[246]
    DIRECTION OUTPUT ;
    USE SIGNAL ;
    SHAPE ABUTMENT ;
    PORT
      LAYER met2 ;
      RECT 871.170 1571.740 871.310 1572.160 ;
    END
  END r0_rd_out[246]
  PIN r0_rd_out[247]
    DIRECTION OUTPUT ;
    USE SIGNAL ;
    SHAPE ABUTMENT ;
    PORT
      LAYER met2 ;
      RECT 878.530 1571.740 878.670 1572.160 ;
    END
  END r0_rd_out[247]
  PIN r0_rd_out[248]
    DIRECTION OUTPUT ;
    USE SIGNAL ;
    SHAPE ABUTMENT ;
    PORT
      LAYER met2 ;
      RECT 885.890 1571.740 886.030 1572.160 ;
    END
  END r0_rd_out[248]
  PIN r0_rd_out[249]
    DIRECTION OUTPUT ;
    USE SIGNAL ;
    SHAPE ABUTMENT ;
    PORT
      LAYER met2 ;
      RECT 893.250 1571.740 893.390 1572.160 ;
    END
  END r0_rd_out[249]
  PIN r0_rd_out[250]
    DIRECTION OUTPUT ;
    USE SIGNAL ;
    SHAPE ABUTMENT ;
    PORT
      LAYER met2 ;
      RECT 900.610 1571.740 900.750 1572.160 ;
    END
  END r0_rd_out[250]
  PIN r0_rd_out[251]
    DIRECTION OUTPUT ;
    USE SIGNAL ;
    SHAPE ABUTMENT ;
    PORT
      LAYER met2 ;
      RECT 907.970 1571.740 908.110 1572.160 ;
    END
  END r0_rd_out[251]
  PIN r0_rd_out[252]
    DIRECTION OUTPUT ;
    USE SIGNAL ;
    SHAPE ABUTMENT ;
    PORT
      LAYER met2 ;
      RECT 915.330 1571.740 915.470 1572.160 ;
    END
  END r0_rd_out[252]
  PIN r0_rd_out[253]
    DIRECTION OUTPUT ;
    USE SIGNAL ;
    SHAPE ABUTMENT ;
    PORT
      LAYER met2 ;
      RECT 922.690 1571.740 922.830 1572.160 ;
    END
  END r0_rd_out[253]
  PIN r0_rd_out[254]
    DIRECTION OUTPUT ;
    USE SIGNAL ;
    SHAPE ABUTMENT ;
    PORT
      LAYER met2 ;
      RECT 930.050 1571.740 930.190 1572.160 ;
    END
  END r0_rd_out[254]
  PIN r0_rd_out[255]
    DIRECTION OUTPUT ;
    USE SIGNAL ;
    SHAPE ABUTMENT ;
    PORT
      LAYER met2 ;
      RECT 937.410 1571.740 937.550 1572.160 ;
    END
  END r0_rd_out[255]
  PIN w0_addr_in[0]
    DIRECTION INPUT ;
    USE SIGNAL ;
    SHAPE ABUTMENT ;
    PORT
      LAYER met3 ;
      RECT 0.000 1353.050 0.900 1353.350 ;
    END
  END w0_addr_in[0]
  PIN w0_addr_in[1]
    DIRECTION INPUT ;
    USE SIGNAL ;
    SHAPE ABUTMENT ;
    PORT
      LAYER met3 ;
      RECT 0.000 1374.130 0.900 1374.430 ;
    END
  END w0_addr_in[1]
  PIN w0_addr_in[2]
    DIRECTION INPUT ;
    USE SIGNAL ;
    SHAPE ABUTMENT ;
    PORT
      LAYER met3 ;
      RECT 0.000 1395.210 0.900 1395.510 ;
    END
  END w0_addr_in[2]
  PIN w0_addr_in[3]
    DIRECTION INPUT ;
    USE SIGNAL ;
    SHAPE ABUTMENT ;
    PORT
      LAYER met3 ;
      RECT 0.000 1416.290 0.900 1416.590 ;
    END
  END w0_addr_in[3]
  PIN w0_addr_in[4]
    DIRECTION INPUT ;
    USE SIGNAL ;
    SHAPE ABUTMENT ;
    PORT
      LAYER met3 ;
      RECT 0.000 1437.370 0.900 1437.670 ;
    END
  END w0_addr_in[4]
  PIN w0_addr_in[5]
    DIRECTION INPUT ;
    USE SIGNAL ;
    SHAPE ABUTMENT ;
    PORT
      LAYER met3 ;
      RECT 989.020 1353.050 989.920 1353.350 ;
    END
  END w0_addr_in[5]
  PIN w0_addr_in[6]
    DIRECTION INPUT ;
    USE SIGNAL ;
    SHAPE ABUTMENT ;
    PORT
      LAYER met3 ;
      RECT 989.020 1374.130 989.920 1374.430 ;
    END
  END w0_addr_in[6]
  PIN w0_addr_in[7]
    DIRECTION INPUT ;
    USE SIGNAL ;
    SHAPE ABUTMENT ;
    PORT
      LAYER met3 ;
      RECT 989.020 1395.210 989.920 1395.510 ;
    END
  END w0_addr_in[7]
  PIN w0_addr_in[8]
    DIRECTION INPUT ;
    USE SIGNAL ;
    SHAPE ABUTMENT ;
    PORT
      LAYER met3 ;
      RECT 989.020 1416.290 989.920 1416.590 ;
    END
  END w0_addr_in[8]
  PIN r0_addr_in[0]
    DIRECTION INPUT ;
    USE SIGNAL ;
    SHAPE ABUTMENT ;
    PORT
      LAYER met3 ;
      RECT 0.000 1458.450 0.900 1458.750 ;
    END
  END r0_addr_in[0]
  PIN r0_addr_in[1]
    DIRECTION INPUT ;
    USE SIGNAL ;
    SHAPE ABUTMENT ;
    PORT
      LAYER met3 ;
      RECT 0.000 1479.530 0.900 1479.830 ;
    END
  END r0_addr_in[1]
  PIN r0_addr_in[2]
    DIRECTION INPUT ;
    USE SIGNAL ;
    SHAPE ABUTMENT ;
    PORT
      LAYER met3 ;
      RECT 0.000 1500.610 0.900 1500.910 ;
    END
  END r0_addr_in[2]
  PIN r0_addr_in[3]
    DIRECTION INPUT ;
    USE SIGNAL ;
    SHAPE ABUTMENT ;
    PORT
      LAYER met3 ;
      RECT 0.000 1521.690 0.900 1521.990 ;
    END
  END r0_addr_in[3]
  PIN r0_addr_in[4]
    DIRECTION INPUT ;
    USE SIGNAL ;
    SHAPE ABUTMENT ;
    PORT
      LAYER met3 ;
      RECT 0.000 1542.770 0.900 1543.070 ;
    END
  END r0_addr_in[4]
  PIN r0_addr_in[5]
    DIRECTION INPUT ;
    USE SIGNAL ;
    SHAPE ABUTMENT ;
    PORT
      LAYER met3 ;
      RECT 989.020 1437.370 989.920 1437.670 ;
    END
  END r0_addr_in[5]
  PIN r0_addr_in[6]
    DIRECTION INPUT ;
    USE SIGNAL ;
    SHAPE ABUTMENT ;
    PORT
      LAYER met3 ;
      RECT 989.020 1458.450 989.920 1458.750 ;
    END
  END r0_addr_in[6]
  PIN r0_addr_in[7]
    DIRECTION INPUT ;
    USE SIGNAL ;
    SHAPE ABUTMENT ;
    PORT
      LAYER met3 ;
      RECT 989.020 1479.530 989.920 1479.830 ;
    END
  END r0_addr_in[7]
  PIN r0_addr_in[8]
    DIRECTION INPUT ;
    USE SIGNAL ;
    SHAPE ABUTMENT ;
    PORT
      LAYER met3 ;
      RECT 989.020 1500.610 989.920 1500.910 ;
    END
  END r0_addr_in[8]
  PIN w0_we_in
    DIRECTION INPUT ;
    USE SIGNAL ;
    SHAPE ABUTMENT ;
    PORT
      LAYER met2 ;
      RECT 944.770 1571.740 944.910 1572.160 ;
    END
  END w0_we_in
  PIN w0_ce_in
    DIRECTION INPUT ;
    USE SIGNAL ;
    SHAPE ABUTMENT ;
    PORT
      LAYER met2 ;
      RECT 952.130 1571.740 952.270 1572.160 ;
    END
  END w0_ce_in
  PIN w0_clk
    DIRECTION INPUT ;
    USE SIGNAL ;
    SHAPE ABUTMENT ;
    PORT
      LAYER met2 ;
      RECT 959.490 1571.740 959.630 1572.160 ;
    END
  END w0_clk
  PIN r0_ce_in
    DIRECTION INPUT ;
    USE SIGNAL ;
    SHAPE ABUTMENT ;
    PORT
      LAYER met2 ;
      RECT 966.850 1571.740 966.990 1572.160 ;
    END
  END r0_ce_in
  PIN r0_clk
    DIRECTION INPUT ;
    USE SIGNAL ;
    SHAPE ABUTMENT ;
    PORT
      LAYER met2 ;
      RECT 974.210 1571.740 974.350 1572.160 ;
    END
  END r0_clk
  PIN VSS
    DIRECTION INOUT ;
    USE GROUND ;
    PORT
      LAYER met4 ;
      RECT 2.160 4.080 3.360 1568.080 ;
      RECT 13.040 4.080 14.240 1568.080 ;
      RECT 23.920 4.080 25.120 1568.080 ;
      RECT 34.800 4.080 36.000 1568.080 ;
      RECT 45.680 4.080 46.880 1568.080 ;
      RECT 56.560 4.080 57.760 1568.080 ;
      RECT 67.440 4.080 68.640 1568.080 ;
      RECT 78.320 4.080 79.520 1568.080 ;
      RECT 89.200 4.080 90.400 1568.080 ;
      RECT 100.080 4.080 101.280 1568.080 ;
      RECT 110.960 4.080 112.160 1568.080 ;
      RECT 121.840 4.080 123.040 1568.080 ;
      RECT 132.720 4.080 133.920 1568.080 ;
      RECT 143.600 4.080 144.800 1568.080 ;
      RECT 154.480 4.080 155.680 1568.080 ;
      RECT 165.360 4.080 166.560 1568.080 ;
      RECT 176.240 4.080 177.440 1568.080 ;
      RECT 187.120 4.080 188.320 1568.080 ;
      RECT 198.000 4.080 199.200 1568.080 ;
      RECT 208.880 4.080 210.080 1568.080 ;
      RECT 219.760 4.080 220.960 1568.080 ;
      RECT 230.640 4.080 231.840 1568.080 ;
      RECT 241.520 4.080 242.720 1568.080 ;
      RECT 252.400 4.080 253.600 1568.080 ;
      RECT 263.280 4.080 264.480 1568.080 ;
      RECT 274.160 4.080 275.360 1568.080 ;
      RECT 285.040 4.080 286.240 1568.080 ;
      RECT 295.920 4.080 297.120 1568.080 ;
      RECT 306.800 4.080 308.000 1568.080 ;
      RECT 317.680 4.080 318.880 1568.080 ;
      RECT 328.560 4.080 329.760 1568.080 ;
      RECT 339.440 4.080 340.640 1568.080 ;
      RECT 350.320 4.080 351.520 1568.080 ;
      RECT 361.200 4.080 362.400 1568.080 ;
      RECT 372.080 4.080 373.280 1568.080 ;
      RECT 382.960 4.080 384.160 1568.080 ;
      RECT 393.840 4.080 395.040 1568.080 ;
      RECT 404.720 4.080 405.920 1568.080 ;
      RECT 415.600 4.080 416.800 1568.080 ;
      RECT 426.480 4.080 427.680 1568.080 ;
      RECT 437.360 4.080 438.560 1568.080 ;
      RECT 448.240 4.080 449.440 1568.080 ;
      RECT 459.120 4.080 460.320 1568.080 ;
      RECT 470.000 4.080 471.200 1568.080 ;
      RECT 480.880 4.080 482.080 1568.080 ;
      RECT 491.760 4.080 492.960 1568.080 ;
      RECT 502.640 4.080 503.840 1568.080 ;
      RECT 513.520 4.080 514.720 1568.080 ;
      RECT 524.400 4.080 525.600 1568.080 ;
      RECT 535.280 4.080 536.480 1568.080 ;
      RECT 546.160 4.080 547.360 1568.080 ;
      RECT 557.040 4.080 558.240 1568.080 ;
      RECT 567.920 4.080 569.120 1568.080 ;
      RECT 578.800 4.080 580.000 1568.080 ;
      RECT 589.680 4.080 590.880 1568.080 ;
      RECT 600.560 4.080 601.760 1568.080 ;
      RECT 611.440 4.080 612.640 1568.080 ;
      RECT 622.320 4.080 623.520 1568.080 ;
      RECT 633.200 4.080 634.400 1568.080 ;
      RECT 644.080 4.080 645.280 1568.080 ;
      RECT 654.960 4.080 656.160 1568.080 ;
      RECT 665.840 4.080 667.040 1568.080 ;
      RECT 676.720 4.080 677.920 1568.080 ;
      RECT 687.600 4.080 688.800 1568.080 ;
      RECT 698.480 4.080 699.680 1568.080 ;
      RECT 709.360 4.080 710.560 1568.080 ;
      RECT 720.240 4.080 721.440 1568.080 ;
      RECT 731.120 4.080 732.320 1568.080 ;
      RECT 742.000 4.080 743.200 1568.080 ;
      RECT 752.880 4.080 754.080 1568.080 ;
      RECT 763.760 4.080 764.960 1568.080 ;
      RECT 774.640 4.080 775.840 1568.080 ;
      RECT 785.520 4.080 786.720 1568.080 ;
      RECT 796.400 4.080 797.600 1568.080 ;
      RECT 807.280 4.080 808.480 1568.080 ;
      RECT 818.160 4.080 819.360 1568.080 ;
      RECT 829.040 4.080 830.240 1568.080 ;
      RECT 839.920 4.080 841.120 1568.080 ;
      RECT 850.800 4.080 852.000 1568.080 ;
      RECT 861.680 4.080 862.880 1568.080 ;
      RECT 872.560 4.080 873.760 1568.080 ;
      RECT 883.440 4.080 884.640 1568.080 ;
      RECT 894.320 4.080 895.520 1568.080 ;
      RECT 905.200 4.080 906.400 1568.080 ;
      RECT 916.080 4.080 917.280 1568.080 ;
      RECT 926.960 4.080 928.160 1568.080 ;
      RECT 937.840 4.080 939.040 1568.080 ;
      RECT 948.720 4.080 949.920 1568.080 ;
      RECT 959.600 4.080 960.800 1568.080 ;
      RECT 970.480 4.080 971.680 1568.080 ;
      RECT 981.360 4.080 982.560 1568.080 ;
    END
  END VSS
  PIN VDD
    DIRECTION INOUT ;
    USE POWER ;
    PORT
      LAYER met4 ;
      RECT 2.160 4.080 3.360 1568.080 ;
      RECT 13.040 4.080 14.240 1568.080 ;
      RECT 23.920 4.080 25.120 1568.080 ;
      RECT 34.800 4.080 36.000 1568.080 ;
      RECT 45.680 4.080 46.880 1568.080 ;
      RECT 56.560 4.080 57.760 1568.080 ;
      RECT 67.440 4.080 68.640 1568.080 ;
      RECT 78.320 4.080 79.520 1568.080 ;
      RECT 89.200 4.080 90.400 1568.080 ;
      RECT 100.080 4.080 101.280 1568.080 ;
      RECT 110.960 4.080 112.160 1568.080 ;
      RECT 121.840 4.080 123.040 1568.080 ;
      RECT 132.720 4.080 133.920 1568.080 ;
      RECT 143.600 4.080 144.800 1568.080 ;
      RECT 154.480 4.080 155.680 1568.080 ;
      RECT 165.360 4.080 166.560 1568.080 ;
      RECT 176.240 4.080 177.440 1568.080 ;
      RECT 187.120 4.080 188.320 1568.080 ;
      RECT 198.000 4.080 199.200 1568.080 ;
      RECT 208.880 4.080 210.080 1568.080 ;
      RECT 219.760 4.080 220.960 1568.080 ;
      RECT 230.640 4.080 231.840 1568.080 ;
      RECT 241.520 4.080 242.720 1568.080 ;
      RECT 252.400 4.080 253.600 1568.080 ;
      RECT 263.280 4.080 264.480 1568.080 ;
      RECT 274.160 4.080 275.360 1568.080 ;
      RECT 285.040 4.080 286.240 1568.080 ;
      RECT 295.920 4.080 297.120 1568.080 ;
      RECT 306.800 4.080 308.000 1568.080 ;
      RECT 317.680 4.080 318.880 1568.080 ;
      RECT 328.560 4.080 329.760 1568.080 ;
      RECT 339.440 4.080 340.640 1568.080 ;
      RECT 350.320 4.080 351.520 1568.080 ;
      RECT 361.200 4.080 362.400 1568.080 ;
      RECT 372.080 4.080 373.280 1568.080 ;
      RECT 382.960 4.080 384.160 1568.080 ;
      RECT 393.840 4.080 395.040 1568.080 ;
      RECT 404.720 4.080 405.920 1568.080 ;
      RECT 415.600 4.080 416.800 1568.080 ;
      RECT 426.480 4.080 427.680 1568.080 ;
      RECT 437.360 4.080 438.560 1568.080 ;
      RECT 448.240 4.080 449.440 1568.080 ;
      RECT 459.120 4.080 460.320 1568.080 ;
      RECT 470.000 4.080 471.200 1568.080 ;
      RECT 480.880 4.080 482.080 1568.080 ;
      RECT 491.760 4.080 492.960 1568.080 ;
      RECT 502.640 4.080 503.840 1568.080 ;
      RECT 513.520 4.080 514.720 1568.080 ;
      RECT 524.400 4.080 525.600 1568.080 ;
      RECT 535.280 4.080 536.480 1568.080 ;
      RECT 546.160 4.080 547.360 1568.080 ;
      RECT 557.040 4.080 558.240 1568.080 ;
      RECT 567.920 4.080 569.120 1568.080 ;
      RECT 578.800 4.080 580.000 1568.080 ;
      RECT 589.680 4.080 590.880 1568.080 ;
      RECT 600.560 4.080 601.760 1568.080 ;
      RECT 611.440 4.080 612.640 1568.080 ;
      RECT 622.320 4.080 623.520 1568.080 ;
      RECT 633.200 4.080 634.400 1568.080 ;
      RECT 644.080 4.080 645.280 1568.080 ;
      RECT 654.960 4.080 656.160 1568.080 ;
      RECT 665.840 4.080 667.040 1568.080 ;
      RECT 676.720 4.080 677.920 1568.080 ;
      RECT 687.600 4.080 688.800 1568.080 ;
      RECT 698.480 4.080 699.680 1568.080 ;
      RECT 709.360 4.080 710.560 1568.080 ;
      RECT 720.240 4.080 721.440 1568.080 ;
      RECT 731.120 4.080 732.320 1568.080 ;
      RECT 742.000 4.080 743.200 1568.080 ;
      RECT 752.880 4.080 754.080 1568.080 ;
      RECT 763.760 4.080 764.960 1568.080 ;
      RECT 774.640 4.080 775.840 1568.080 ;
      RECT 785.520 4.080 786.720 1568.080 ;
      RECT 796.400 4.080 797.600 1568.080 ;
      RECT 807.280 4.080 808.480 1568.080 ;
      RECT 818.160 4.080 819.360 1568.080 ;
      RECT 829.040 4.080 830.240 1568.080 ;
      RECT 839.920 4.080 841.120 1568.080 ;
      RECT 850.800 4.080 852.000 1568.080 ;
      RECT 861.680 4.080 862.880 1568.080 ;
      RECT 872.560 4.080 873.760 1568.080 ;
      RECT 883.440 4.080 884.640 1568.080 ;
      RECT 894.320 4.080 895.520 1568.080 ;
      RECT 905.200 4.080 906.400 1568.080 ;
      RECT 916.080 4.080 917.280 1568.080 ;
      RECT 926.960 4.080 928.160 1568.080 ;
      RECT 937.840 4.080 939.040 1568.080 ;
      RECT 948.720 4.080 949.920 1568.080 ;
      RECT 959.600 4.080 960.800 1568.080 ;
      RECT 970.480 4.080 971.680 1568.080 ;
      RECT 981.360 4.080 982.560 1568.080 ;
    END
  END VDD
  OBS
    LAYER met1 ;
    RECT 0 0 989.920 1572.160 ;
    LAYER met2 ;
    RECT 0 0 989.920 1572.160 ;
    LAYER met3 ;
    RECT 0 0 989.920 1572.160 ;
    LAYER met4 ;
    RECT 0 0 989.920 1572.160 ;
  END
END fakeram_256x512_1r1w

END LIBRARY
